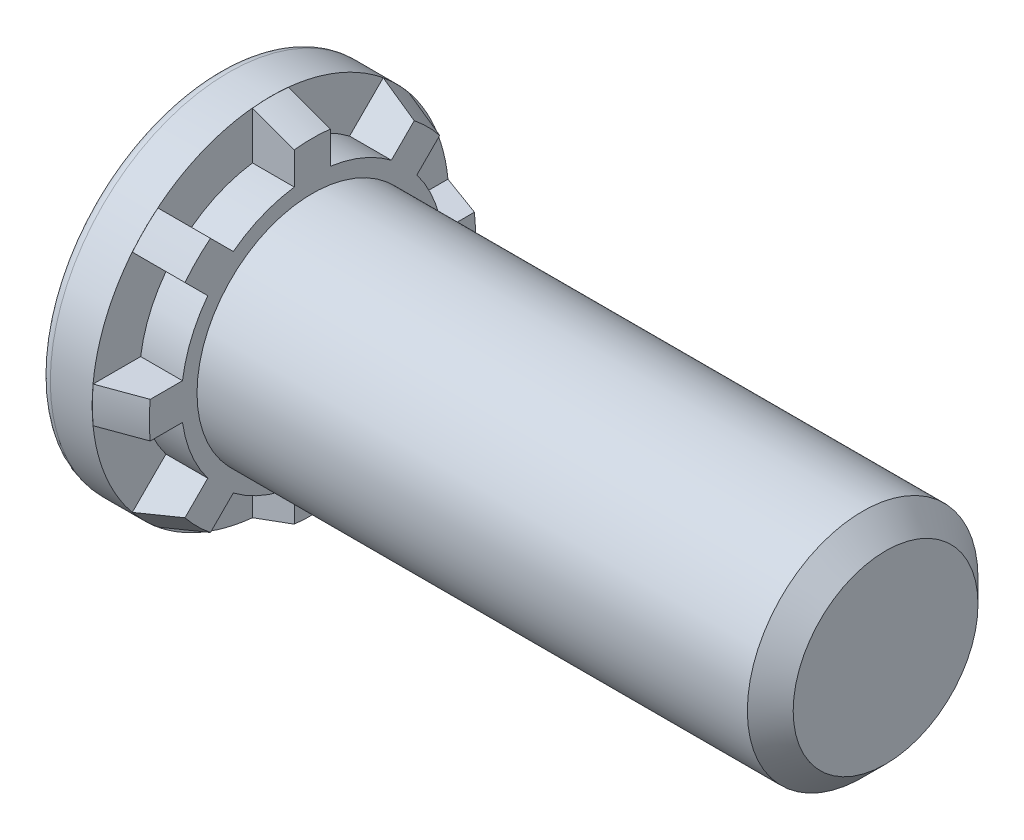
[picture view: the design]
ISO-10303-21;
HEADER;
FILE_DESCRIPTION(('STEP AP214'),'2;1');
FILE_NAME('part.step','',(''),(''),'','','');
FILE_SCHEMA(('AUTOMOTIVE_DESIGN { 1 0 10303 214 1 1 1 1 }'));
ENDSEC;
DATA;
#1=APPLICATION_CONTEXT('core data for automotive mechanical design processes');
#2=APPLICATION_PROTOCOL_DEFINITION('international standard','automotive_design',2000,#1);
#3=PRODUCT_CONTEXT('',#1,'mechanical');
#4=PRODUCT('Part','Part','',(#3));
#5=PRODUCT_RELATED_PRODUCT_CATEGORY('part','',(#4));
#6=PRODUCT_DEFINITION_FORMATION('','',#4);
#7=PRODUCT_DEFINITION_CONTEXT('part definition',#1,'design');
#8=PRODUCT_DEFINITION('design','',#6,#7);
#9=PRODUCT_DEFINITION_SHAPE('','',#8);
#10=(LENGTH_UNIT() NAMED_UNIT(*) SI_UNIT(.MILLI.,.METRE.));
#11=(NAMED_UNIT(*) PLANE_ANGLE_UNIT() SI_UNIT($,.RADIAN.));
#12=(NAMED_UNIT(*) SI_UNIT($,.STERADIAN.) SOLID_ANGLE_UNIT());
#13=UNCERTAINTY_MEASURE_WITH_UNIT(LENGTH_MEASURE(1.E-05),#10,'distance_accuracy_value','');
#14=(GEOMETRIC_REPRESENTATION_CONTEXT(3) GLOBAL_UNCERTAINTY_ASSIGNED_CONTEXT((#13)) GLOBAL_UNIT_ASSIGNED_CONTEXT((#10,
#11,#12)) REPRESENTATION_CONTEXT('',''));
#15=CARTESIAN_POINT('',(0.,0.,0.));
#16=DIRECTION('',(0.,0.,1.));
#17=DIRECTION('',(1.,0.,0.));
#18=AXIS2_PLACEMENT_3D('',#15,#16,#17);
#19=CARTESIAN_POINT('',(0.00254,0.,0.));
#20=DIRECTION('',(-1.,0.,0.));
#21=DIRECTION('',(0.,0.,1.));
#22=AXIS2_PLACEMENT_3D('',#19,#20,#21);
#23=CONICAL_SURFACE('',#22,7.36346,0.349065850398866);
#24=CARTESIAN_POINT('',(1.72739999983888,4.20680011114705,5.26041628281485));
#25=CARTESIAN_POINT('',(1.43990711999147,4.28124598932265,5.33486216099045));
#26=CARTESIAN_POINT('',(1.15240568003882,4.35567533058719,5.40929150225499));
#27=CARTESIAN_POINT('',(0.577385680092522,4.5045009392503,5.55811711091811));
#28=CARTESIAN_POINT('',(0.28986712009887,4.57889720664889,5.6325133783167));
#29=CARTESIAN_POINT('',(0.00233999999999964,4.65327693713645,5.70689310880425));
#30=B_SPLINE_CURVE_WITH_KNOTS('',3,(#24,#25,#26,#27,#28,#29),.UNSPECIFIED.,.F.,.F.,(4,2,4),(0.,
0.918492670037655,1.83698533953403),.UNSPECIFIED.);
#31=CARTESIAN_POINT('',(1.72719999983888,4.20685190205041,5.26046807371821));
#32=VERTEX_POINT('',#31);
#33=CARTESIAN_POINT('',(0.00254,4.65322519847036,5.70684137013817));
#34=VERTEX_POINT('',#33);
#35=EDGE_CURVE('E558',#32,#34,#30,.T.);
#36=ORIENTED_EDGE('',*,*,#35,.F.);
#37=CARTESIAN_POINT('',(1.7272,0.,0.));
#38=DIRECTION('',(-1.,0.,0.));
#39=DIRECTION('',(0.,0.,1.));
#40=AXIS2_PLACEMENT_3D('',#37,#38,#39);
#41=CIRCLE('',#40,6.73573509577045);
#42=CARTESIAN_POINT('',(1.72719999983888,5.2604680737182,4.20685190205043));
#43=VERTEX_POINT('',#42);
#44=EDGE_CURVE('E559',#32,#43,#41,.T.);
#45=ORIENTED_EDGE('',*,*,#44,.T.);
#46=CARTESIAN_POINT('',(0.00234000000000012,5.70689310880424,4.65327693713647));
#47=CARTESIAN_POINT('',(0.28986712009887,5.63251337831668,4.57889720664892));
#48=CARTESIAN_POINT('',(0.577385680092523,5.55811711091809,4.50450093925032));
#49=CARTESIAN_POINT('',(1.15240568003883,5.40929150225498,4.35567533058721));
#50=CARTESIAN_POINT('',(1.43990711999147,5.33486216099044,4.28124598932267));
#51=CARTESIAN_POINT('',(1.72739999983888,5.26041628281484,4.20680011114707));
#52=B_SPLINE_CURVE_WITH_KNOTS('',3,(#46,#47,#48,#49,#50,#51),.UNSPECIFIED.,.F.,.F.,(4,2,4),(0.,
0.918492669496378,1.83698533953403),.UNSPECIFIED.);
#53=CARTESIAN_POINT('',(0.00254,5.70684137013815,4.65322519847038));
#54=VERTEX_POINT('',#53);
#55=EDGE_CURVE('E457',#54,#43,#52,.T.);
#56=ORIENTED_EDGE('',*,*,#55,.F.);
#57=CARTESIAN_POINT('',(0.00254,0.,0.));
#58=DIRECTION('',(-1.,0.,0.));
#59=DIRECTION('',(0.,0.,1.));
#60=AXIS2_PLACEMENT_3D('',#57,#58,#59);
#61=CIRCLE('',#60,7.36346);
#62=EDGE_CURVE('E561',#34,#54,#61,.T.);
#63=ORIENTED_EDGE('',*,*,#62,.F.);
#64=EDGE_LOOP('',(#36,#45,#56,#63));
#65=FACE_BOUND('',#64,.T.);
#66=ADVANCED_FACE('F39',(#65),#23,.T.);
#67=CARTESIAN_POINT('',(1.72739999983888,-5.26041628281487,4.20680011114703));
#68=CARTESIAN_POINT('',(1.43990711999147,-5.33486216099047,4.28124598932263));
#69=CARTESIAN_POINT('',(1.15240568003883,-5.40929150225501,4.35567533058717));
#70=CARTESIAN_POINT('',(0.577385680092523,-5.55811711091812,4.50450093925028));
#71=CARTESIAN_POINT('',(0.28986712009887,-5.63251337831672,4.57889720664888));
#72=CARTESIAN_POINT('',(0.00234000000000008,-5.70689310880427,4.65327693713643));
#73=B_SPLINE_CURVE_WITH_KNOTS('',3,(#67,#68,#69,#70,#71,#72),.UNSPECIFIED.,.F.,.F.,(4,2,4),(0.,
0.918492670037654,1.83698533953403),.UNSPECIFIED.);
#74=CARTESIAN_POINT('',(1.72719999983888,-5.26046807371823,4.20685190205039));
#75=VERTEX_POINT('',#74);
#76=CARTESIAN_POINT('',(0.00254,-5.70684137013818,4.65322519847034));
#77=VERTEX_POINT('',#76);
#78=EDGE_CURVE('E607',#75,#77,#73,.T.);
#79=ORIENTED_EDGE('',*,*,#78,.F.);
#80=CARTESIAN_POINT('',(1.72719999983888,-4.20685190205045,5.26046807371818));
#81=VERTEX_POINT('',#80);
#82=EDGE_CURVE('E572',#75,#81,#41,.T.);
#83=ORIENTED_EDGE('',*,*,#82,.T.);
#84=CARTESIAN_POINT('',(0.00234000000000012,-4.65327693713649,5.70689310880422));
#85=CARTESIAN_POINT('',(0.28986712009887,-4.57889720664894,5.63251337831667));
#86=CARTESIAN_POINT('',(0.577385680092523,-4.50450093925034,5.55811711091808));
#87=CARTESIAN_POINT('',(1.15240568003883,-4.35567533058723,5.40929150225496));
#88=CARTESIAN_POINT('',(1.43990711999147,-4.28124598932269,5.33486216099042));
#89=CARTESIAN_POINT('',(1.72739999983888,-4.20680011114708,5.26041628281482));
#90=B_SPLINE_CURVE_WITH_KNOTS('',3,(#84,#85,#86,#87,#88,#89),.UNSPECIFIED.,.F.,.F.,(4,2,4),(0.,
0.918492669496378,1.83698533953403),.UNSPECIFIED.);
#91=CARTESIAN_POINT('',(0.00254,-4.6532251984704,5.70684137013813));
#92=VERTEX_POINT('',#91);
#93=EDGE_CURVE('E610',#92,#81,#90,.T.);
#94=ORIENTED_EDGE('',*,*,#93,.F.);
#95=EDGE_CURVE('E750',#77,#92,#61,.T.);
#96=ORIENTED_EDGE('',*,*,#95,.F.);
#97=EDGE_LOOP('',(#79,#83,#94,#96));
#98=FACE_BOUND('',#97,.T.);
#99=ADVANCED_FACE('F550',(#98),#23,.T.);
#100=CARTESIAN_POINT('',(-4.27246553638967,0.74501913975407,8.88826546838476));
#101=CARTESIAN_POINT('',(-3.51512222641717,0.745019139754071,8.61164424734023));
#102=CARTESIAN_POINT('',(-2.75780524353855,0.745019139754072,8.33495090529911));
#103=CARTESIAN_POINT('',(-1.24325020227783,0.745019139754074,7.78134871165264));
#104=CARTESIAN_POINT('',(-0.4860121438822,0.745019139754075,7.50443986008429));
#105=CARTESIAN_POINT('',(1.02835911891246,0.745019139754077,6.95033525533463));
#106=CARTESIAN_POINT('',(1.78549232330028,0.745019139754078,6.67313950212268));
#107=CARTESIAN_POINT('',(3.29960004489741,0.74501913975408,6.11831457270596));
#108=CARTESIAN_POINT('',(4.05657456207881,0.745019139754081,5.84068539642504));
#109=CARTESIAN_POINT('',(4.81344272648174,0.745019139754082,5.56276628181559));
#110=B_SPLINE_CURVE_WITH_KNOTS('',3,(#100,#101,#102,#103,#104,#105,#106,#107,#108,#109),
.UNSPECIFIED.,.F.,.F.,(4,2,2,2,4),(0.,2.41884141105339,4.83768240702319,7.25652366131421,
9.67536534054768),.UNSPECIFIED.);
#111=CARTESIAN_POINT('',(0.00254,0.745019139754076,7.32567332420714));
#112=VERTEX_POINT('',#111);
#113=CARTESIAN_POINT('',(1.72719999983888,0.745019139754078,6.69440615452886));
#114=VERTEX_POINT('',#113);
#115=EDGE_CURVE('E562',#112,#114,#110,.T.);
#116=ORIENTED_EDGE('',*,*,#115,.F.);
#117=CARTESIAN_POINT('',(0.00254,-0.745019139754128,7.32567332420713));
#118=VERTEX_POINT('',#117);
#119=EDGE_CURVE('E676',#118,#112,#61,.T.);
#120=ORIENTED_EDGE('',*,*,#119,.F.);
#121=CARTESIAN_POINT('',(4.81344272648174,-0.745019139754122,5.56276628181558));
#122=CARTESIAN_POINT('',(4.05657456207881,-0.745019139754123,5.84068539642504));
#123=CARTESIAN_POINT('',(3.29960004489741,-0.745019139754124,6.11831457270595));
#124=CARTESIAN_POINT('',(1.78549232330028,-0.745019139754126,6.67313950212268));
#125=CARTESIAN_POINT('',(1.02835911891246,-0.745019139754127,6.95033525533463));
#126=CARTESIAN_POINT('',(-0.486012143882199,-0.745019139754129,7.50443986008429));
#127=CARTESIAN_POINT('',(-1.24325020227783,-0.74501913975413,7.78134871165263));
#128=CARTESIAN_POINT('',(-2.75780524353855,-0.745019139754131,8.3349509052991));
#129=CARTESIAN_POINT('',(-3.51512222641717,-0.745019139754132,8.61164424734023));
#130=CARTESIAN_POINT('',(-4.27246553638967,-0.745019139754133,8.88826546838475));
#131=B_SPLINE_CURVE_WITH_KNOTS('',3,(#121,#122,#123,#124,#125,#126,#127,#128,#129,#130),
.UNSPECIFIED.,.F.,.F.,(4,2,2,2,4),(0.,2.41884167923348,4.83768293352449,7.25652392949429,
9.67536534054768),.UNSPECIFIED.);
#132=CARTESIAN_POINT('',(1.72719999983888,-0.745019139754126,6.69440615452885));
#133=VERTEX_POINT('',#132);
#134=EDGE_CURVE('E630',#133,#118,#131,.T.);
#135=ORIENTED_EDGE('',*,*,#134,.F.);
#136=EDGE_CURVE('E568',#133,#114,#41,.T.);
#137=ORIENTED_EDGE('',*,*,#136,.T.);
#138=EDGE_LOOP('',(#116,#120,#135,#137));
#139=FACE_BOUND('',#138,.T.);
#140=ADVANCED_FACE('F552',(#139),#23,.T.);
#141=CARTESIAN_POINT('',(4.81344272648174,0.74501913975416,-5.56276628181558));
#142=CARTESIAN_POINT('',(4.05657456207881,0.745019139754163,-5.84068539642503));
#143=CARTESIAN_POINT('',(3.29960004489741,0.745019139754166,-6.11831457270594));
#144=CARTESIAN_POINT('',(1.78549232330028,0.745019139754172,-6.67313950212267));
#145=CARTESIAN_POINT('',(1.02835911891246,0.745019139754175,-6.95033525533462));
#146=CARTESIAN_POINT('',(-0.486012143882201,0.745019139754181,-7.50443986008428));
#147=CARTESIAN_POINT('',(-1.24325020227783,0.745019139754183,-7.78134871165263));
#148=CARTESIAN_POINT('',(-2.75780524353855,0.745019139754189,-8.3349509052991));
#149=CARTESIAN_POINT('',(-3.51512222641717,0.745019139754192,-8.61164424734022));
#150=CARTESIAN_POINT('',(-4.27246553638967,0.745019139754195,-8.88826546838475));
#151=B_SPLINE_CURVE_WITH_KNOTS('',3,(#141,#142,#143,#144,#145,#146,#147,#148,#149,#150),
.UNSPECIFIED.,.F.,.F.,(4,2,2,2,4),(0.,2.41884167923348,4.83768293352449,7.2565239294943,
9.67536534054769),.UNSPECIFIED.);
#152=CARTESIAN_POINT('',(1.72719999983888,0.745019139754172,-6.69440615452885));
#153=VERTEX_POINT('',#152);
#154=CARTESIAN_POINT('',(0.00254,0.745019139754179,-7.32567332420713));
#155=VERTEX_POINT('',#154);
#156=EDGE_CURVE('E693',#153,#155,#151,.T.);
#157=ORIENTED_EDGE('',*,*,#156,.F.);
#158=CARTESIAN_POINT('',(1.72719999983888,-0.745019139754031,-6.69440615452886));
#159=VERTEX_POINT('',#158);
#160=EDGE_CURVE('E574',#153,#159,#41,.T.);
#161=ORIENTED_EDGE('',*,*,#160,.T.);
#162=CARTESIAN_POINT('',(-4.27246553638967,-0.745019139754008,-8.88826546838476));
#163=CARTESIAN_POINT('',(-3.51512222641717,-0.745019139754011,-8.61164424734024));
#164=CARTESIAN_POINT('',(-2.75780524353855,-0.745019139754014,-8.33495090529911));
#165=CARTESIAN_POINT('',(-1.24325020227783,-0.74501913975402,-7.78134871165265));
#166=CARTESIAN_POINT('',(-0.4860121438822,-0.745019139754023,-7.5044398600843));
#167=CARTESIAN_POINT('',(1.02835911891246,-0.745019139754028,-6.95033525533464));
#168=CARTESIAN_POINT('',(1.78549232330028,-0.745019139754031,-6.67313950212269));
#169=CARTESIAN_POINT('',(3.29960004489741,-0.745019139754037,-6.11831457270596));
#170=CARTESIAN_POINT('',(4.05657456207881,-0.74501913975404,-5.84068539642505));
#171=CARTESIAN_POINT('',(4.81344272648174,-0.745019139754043,-5.56276628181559));
#172=B_SPLINE_CURVE_WITH_KNOTS('',3,(#162,#163,#164,#165,#166,#167,#168,#169,#170,#171),
.UNSPECIFIED.,.F.,.F.,(4,2,2,2,4),(0.,2.41884141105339,4.83768240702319,7.25652366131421,
9.67536534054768),.UNSPECIFIED.);
#173=CARTESIAN_POINT('',(0.00254,-0.745019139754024,-7.32567332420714));
#174=VERTEX_POINT('',#173);
#175=EDGE_CURVE('E700',#174,#159,#172,.T.);
#176=ORIENTED_EDGE('',*,*,#175,.F.);
#177=EDGE_CURVE('E673',#155,#174,#61,.T.);
#178=ORIENTED_EDGE('',*,*,#177,.F.);
#179=EDGE_LOOP('',(#157,#161,#176,#178));
#180=FACE_BOUND('',#179,.T.);
#181=ADVANCED_FACE('F935',(#180),#23,.T.);
#182=CARTESIAN_POINT('',(1.72739999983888,-4.20680011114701,-5.26041628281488));
#183=CARTESIAN_POINT('',(1.43990711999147,-4.28124598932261,-5.33486216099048));
#184=CARTESIAN_POINT('',(1.15240568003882,-4.35567533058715,-5.40929150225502));
#185=CARTESIAN_POINT('',(0.577385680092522,-4.50450093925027,-5.55811711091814));
#186=CARTESIAN_POINT('',(0.28986712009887,-4.57889720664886,-5.63251337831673));
#187=CARTESIAN_POINT('',(0.00233999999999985,-4.65327693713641,-5.70689310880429));
#188=B_SPLINE_CURVE_WITH_KNOTS('',3,(#182,#183,#184,#185,#186,#187),.UNSPECIFIED.,.F.,.F.,(4,2,
4),(0.,0.918492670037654,1.83698533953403),.UNSPECIFIED.);
#189=CARTESIAN_POINT('',(1.72719999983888,-4.20685190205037,-5.26046807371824));
#190=VERTEX_POINT('',#189);
#191=CARTESIAN_POINT('',(0.00254,-4.65322519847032,-5.7068413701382));
#192=VERTEX_POINT('',#191);
#193=EDGE_CURVE('E692',#190,#192,#188,.T.);
#194=ORIENTED_EDGE('',*,*,#193,.F.);
#195=CARTESIAN_POINT('',(1.72719999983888,-5.26046807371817,-4.20685190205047));
#196=VERTEX_POINT('',#195);
#197=EDGE_CURVE('E588',#190,#196,#41,.T.);
#198=ORIENTED_EDGE('',*,*,#197,.T.);
#199=CARTESIAN_POINT('',(0.00234000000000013,-5.7068931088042,-4.65327693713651));
#200=CARTESIAN_POINT('',(0.28986712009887,-5.63251337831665,-4.57889720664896));
#201=CARTESIAN_POINT('',(0.577385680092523,-5.55811711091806,-4.50450093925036));
#202=CARTESIAN_POINT('',(1.15240568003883,-5.40929150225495,-4.35567533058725));
#203=CARTESIAN_POINT('',(1.43990711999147,-5.33486216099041,-4.2812459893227));
#204=CARTESIAN_POINT('',(1.72739999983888,-5.26041628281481,-4.2068001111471));
#205=B_SPLINE_CURVE_WITH_KNOTS('',3,(#199,#200,#201,#202,#203,#204),.UNSPECIFIED.,.F.,.F.,(4,2,
4),(0.,0.918492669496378,1.83698533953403),.UNSPECIFIED.);
#206=CARTESIAN_POINT('',(0.00254,-5.70684137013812,-4.65322519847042));
#207=VERTEX_POINT('',#206);
#208=EDGE_CURVE('E330',#207,#196,#205,.T.);
#209=ORIENTED_EDGE('',*,*,#208,.F.);
#210=EDGE_CURVE('E680',#192,#207,#61,.T.);
#211=ORIENTED_EDGE('',*,*,#210,.F.);
#212=EDGE_LOOP('',(#194,#198,#209,#211));
#213=FACE_BOUND('',#212,.T.);
#214=ADVANCED_FACE('F928',(#213),#23,.T.);
#215=CARTESIAN_POINT('',(-4.27246553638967,-8.88826546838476,0.745019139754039));
#216=CARTESIAN_POINT('',(-3.51512222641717,-8.61164424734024,0.745019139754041));
#217=CARTESIAN_POINT('',(-2.75780524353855,-8.33495090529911,0.745019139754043));
#218=CARTESIAN_POINT('',(-1.24325020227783,-7.78134871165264,0.745019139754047));
#219=CARTESIAN_POINT('',(-0.486012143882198,-7.5044398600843,0.745019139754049));
#220=CARTESIAN_POINT('',(1.02835911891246,-6.95033525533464,0.745019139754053));
#221=CARTESIAN_POINT('',(1.78549232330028,-6.67313950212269,0.745019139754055));
#222=CARTESIAN_POINT('',(3.29960004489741,-6.11831457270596,0.745019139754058));
#223=CARTESIAN_POINT('',(4.05657456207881,-5.84068539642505,0.74501913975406));
#224=CARTESIAN_POINT('',(4.81344272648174,-5.56276628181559,0.745019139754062));
#225=B_SPLINE_CURVE_WITH_KNOTS('',3,(#215,#216,#217,#218,#219,#220,#221,#222,#223,#224),
.UNSPECIFIED.,.F.,.F.,(4,2,2,2,4),(0.,2.41884141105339,4.83768240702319,7.25652366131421,
9.67536534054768),.UNSPECIFIED.);
#226=CARTESIAN_POINT('',(0.00254,-7.32567332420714,0.74501913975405));
#227=VERTEX_POINT('',#226);
#228=CARTESIAN_POINT('',(1.72719999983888,-6.69440615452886,0.745019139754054));
#229=VERTEX_POINT('',#228);
#230=EDGE_CURVE('E746',#227,#229,#225,.T.);
#231=ORIENTED_EDGE('',*,*,#230,.F.);
#232=CARTESIAN_POINT('',(0.00254,-7.32567332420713,-0.745019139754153));
#233=VERTEX_POINT('',#232);
#234=EDGE_CURVE('E745',#233,#227,#61,.T.);
#235=ORIENTED_EDGE('',*,*,#234,.F.);
#236=CARTESIAN_POINT('',(4.81344272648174,-5.56276628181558,-0.745019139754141));
#237=CARTESIAN_POINT('',(4.05657456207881,-5.84068539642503,-0.745019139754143));
#238=CARTESIAN_POINT('',(3.29960004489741,-6.11831457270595,-0.745019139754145));
#239=CARTESIAN_POINT('',(1.78549232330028,-6.67313950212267,-0.745019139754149));
#240=CARTESIAN_POINT('',(1.02835911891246,-6.95033525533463,-0.745019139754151));
#241=CARTESIAN_POINT('',(-0.4860121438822,-7.50443986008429,-0.745019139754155));
#242=CARTESIAN_POINT('',(-1.24325020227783,-7.78134871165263,-0.745019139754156));
#243=CARTESIAN_POINT('',(-2.75780524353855,-8.3349509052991,-0.74501913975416));
#244=CARTESIAN_POINT('',(-3.51512222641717,-8.61164424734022,-0.745019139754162));
#245=CARTESIAN_POINT('',(-4.27246553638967,-8.88826546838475,-0.745019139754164));
#246=B_SPLINE_CURVE_WITH_KNOTS('',3,(#236,#237,#238,#239,#240,#241,#242,#243,#244,#245),
.UNSPECIFIED.,.F.,.F.,(4,2,2,2,4),(0.,2.41884167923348,4.83768293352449,7.2565239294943,
9.67536534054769),.UNSPECIFIED.);
#247=CARTESIAN_POINT('',(1.72719999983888,-6.69440615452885,-0.745019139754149));
#248=VERTEX_POINT('',#247);
#249=EDGE_CURVE('E430',#248,#233,#246,.T.);
#250=ORIENTED_EDGE('',*,*,#249,.F.);
#251=EDGE_CURVE('E595',#248,#229,#41,.T.);
#252=ORIENTED_EDGE('',*,*,#251,.T.);
#253=EDGE_LOOP('',(#231,#235,#250,#252));
#254=FACE_BOUND('',#253,.T.);
#255=ADVANCED_FACE('F747',(#254),#23,.T.);
#256=CARTESIAN_POINT('',(0.,0.,0.));
#257=DIRECTION('',(-1.,0.,0.));
#258=DIRECTION('',(0.,0.,1.));
#259=AXIS2_PLACEMENT_3D('',#256,#257,#258);
#260=CYLINDRICAL_SURFACE('',#259,7.36346);
#261=CARTESIAN_POINT('',(0.,0.,0.));
#262=DIRECTION('',(-1.,0.,0.));
#263=DIRECTION('',(0.,0.,1.));
#264=AXIS2_PLACEMENT_3D('',#261,#262,#263);
#265=CIRCLE('',#264,7.36346);
#266=CARTESIAN_POINT('',(0.,4.65322519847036,5.70684137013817));
#267=VERTEX_POINT('',#266);
#268=CARTESIAN_POINT('',(-1.61121766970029E-10,5.70684137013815,4.65322519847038));
#269=VERTEX_POINT('',#268);
#270=EDGE_CURVE('E636',#267,#269,#265,.T.);
#271=ORIENTED_EDGE('',*,*,#270,.F.);
#272=DIRECTION('',(-1.,0.,0.));
#273=VECTOR('',#272,1.);
#274=CARTESIAN_POINT('',(0.,4.65322519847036,5.70684137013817));
#275=LINE('',#274,#273);
#276=EDGE_CURVE('E11',#267,#34,#275,.F.);
#277=ORIENTED_EDGE('',*,*,#276,.T.);
#278=ORIENTED_EDGE('',*,*,#62,.T.);
#279=DIRECTION('',(-1.,0.,0.));
#280=VECTOR('',#279,1.);
#281=CARTESIAN_POINT('',(0.,5.70684137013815,4.65322519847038));
#282=LINE('',#281,#280);
#283=EDGE_CURVE('E686',#54,#269,#282,.T.);
#284=ORIENTED_EDGE('',*,*,#283,.T.);
#285=EDGE_LOOP('',(#271,#277,#278,#284));
#286=FACE_BOUND('',#285,.T.);
#287=ADVANCED_FACE('F508',(#286),#260,.T.);
#288=CARTESIAN_POINT('',(0.,-5.70684137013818,4.65322519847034));
#289=VERTEX_POINT('',#288);
#290=CARTESIAN_POINT('',(-1.61121766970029E-10,-4.6532251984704,5.70684137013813));
#291=VERTEX_POINT('',#290);
#292=EDGE_CURVE('E634',#289,#291,#265,.T.);
#293=ORIENTED_EDGE('',*,*,#292,.F.);
#294=DIRECTION('',(-1.,0.,0.));
#295=VECTOR('',#294,1.);
#296=CARTESIAN_POINT('',(0.,-5.70684137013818,4.65322519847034));
#297=LINE('',#296,#295);
#298=EDGE_CURVE('E859',#289,#77,#297,.F.);
#299=ORIENTED_EDGE('',*,*,#298,.T.);
#300=ORIENTED_EDGE('',*,*,#95,.T.);
#301=DIRECTION('',(-1.,0.,0.));
#302=VECTOR('',#301,1.);
#303=CARTESIAN_POINT('',(0.,-4.6532251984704,5.70684137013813));
#304=LINE('',#303,#302);
#305=EDGE_CURVE('E635',#92,#291,#304,.T.);
#306=ORIENTED_EDGE('',*,*,#305,.T.);
#307=EDGE_LOOP('',(#293,#299,#300,#306));
#308=FACE_BOUND('',#307,.T.);
#309=ADVANCED_FACE('F865',(#308),#260,.T.);
#310=ORIENTED_EDGE('',*,*,#119,.T.);
#311=DIRECTION('',(-1.,0.,0.));
#312=VECTOR('',#311,1.);
#313=CARTESIAN_POINT('',(0.,0.745019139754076,7.32567332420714));
#314=LINE('',#313,#312);
#315=CARTESIAN_POINT('',(-1.61121766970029E-10,0.745019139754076,7.32567332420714));
#316=VERTEX_POINT('',#315);
#317=EDGE_CURVE('E48',#112,#316,#314,.T.);
#318=ORIENTED_EDGE('',*,*,#317,.T.);
#319=CARTESIAN_POINT('',(0.,-0.745019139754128,7.32567332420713));
#320=VERTEX_POINT('',#319);
#321=EDGE_CURVE('E303',#320,#316,#265,.T.);
#322=ORIENTED_EDGE('',*,*,#321,.F.);
#323=DIRECTION('',(-1.,0.,0.));
#324=VECTOR('',#323,1.);
#325=CARTESIAN_POINT('',(0.,-0.745019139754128,7.32567332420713));
#326=LINE('',#325,#324);
#327=EDGE_CURVE('E622',#320,#118,#326,.F.);
#328=ORIENTED_EDGE('',*,*,#327,.T.);
#329=EDGE_LOOP('',(#310,#318,#322,#328));
#330=FACE_BOUND('',#329,.T.);
#331=ADVANCED_FACE('F632',(#330),#260,.T.);
#332=CARTESIAN_POINT('',(0.,0.745019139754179,-7.32567332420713));
#333=VERTEX_POINT('',#332);
#334=CARTESIAN_POINT('',(-1.61121766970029E-10,-0.745019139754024,-7.32567332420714));
#335=VERTEX_POINT('',#334);
#336=EDGE_CURVE('E641',#333,#335,#265,.T.);
#337=ORIENTED_EDGE('',*,*,#336,.F.);
#338=DIRECTION('',(-1.,0.,0.));
#339=VECTOR('',#338,1.);
#340=CARTESIAN_POINT('',(0.,0.745019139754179,-7.32567332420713));
#341=LINE('',#340,#339);
#342=EDGE_CURVE('E862',#333,#155,#341,.F.);
#343=ORIENTED_EDGE('',*,*,#342,.T.);
#344=ORIENTED_EDGE('',*,*,#177,.T.);
#345=DIRECTION('',(-1.,0.,0.));
#346=VECTOR('',#345,1.);
#347=CARTESIAN_POINT('',(0.,-0.745019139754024,-7.32567332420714));
#348=LINE('',#347,#346);
#349=EDGE_CURVE('E742',#174,#335,#348,.T.);
#350=ORIENTED_EDGE('',*,*,#349,.T.);
#351=EDGE_LOOP('',(#337,#343,#344,#350));
#352=FACE_BOUND('',#351,.T.);
#353=ADVANCED_FACE('F841',(#352),#260,.T.);
#354=CARTESIAN_POINT('',(0.,-4.65322519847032,-5.7068413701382));
#355=VERTEX_POINT('',#354);
#356=CARTESIAN_POINT('',(-1.61121766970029E-10,-5.70684137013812,-4.65322519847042));
#357=VERTEX_POINT('',#356);
#358=EDGE_CURVE('E850',#355,#357,#265,.T.);
#359=ORIENTED_EDGE('',*,*,#358,.F.);
#360=DIRECTION('',(-1.,0.,0.));
#361=VECTOR('',#360,1.);
#362=CARTESIAN_POINT('',(0.,-4.65322519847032,-5.7068413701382));
#363=LINE('',#362,#361);
#364=EDGE_CURVE('E842',#355,#192,#363,.F.);
#365=ORIENTED_EDGE('',*,*,#364,.T.);
#366=ORIENTED_EDGE('',*,*,#210,.T.);
#367=DIRECTION('',(-1.,0.,0.));
#368=VECTOR('',#367,1.);
#369=CARTESIAN_POINT('',(0.,-5.70684137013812,-4.65322519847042));
#370=LINE('',#369,#368);
#371=EDGE_CURVE('E744',#207,#357,#370,.T.);
#372=ORIENTED_EDGE('',*,*,#371,.T.);
#373=EDGE_LOOP('',(#359,#365,#366,#372));
#374=FACE_BOUND('',#373,.T.);
#375=ADVANCED_FACE('F917',(#374),#260,.T.);
#376=ORIENTED_EDGE('',*,*,#234,.T.);
#377=DIRECTION('',(-1.,0.,0.));
#378=VECTOR('',#377,1.);
#379=CARTESIAN_POINT('',(0.,-7.32567332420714,0.74501913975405));
#380=LINE('',#379,#378);
#381=CARTESIAN_POINT('',(-1.61121766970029E-10,-7.32567332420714,0.74501913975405));
#382=VERTEX_POINT('',#381);
#383=EDGE_CURVE('E631',#227,#382,#380,.T.);
#384=ORIENTED_EDGE('',*,*,#383,.T.);
#385=CARTESIAN_POINT('',(0.,-7.32567332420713,-0.745019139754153));
#386=VERTEX_POINT('',#385);
#387=EDGE_CURVE('E637',#386,#382,#265,.T.);
#388=ORIENTED_EDGE('',*,*,#387,.F.);
#389=DIRECTION('',(-1.,0.,0.));
#390=VECTOR('',#389,1.);
#391=CARTESIAN_POINT('',(0.,-7.32567332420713,-0.745019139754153));
#392=LINE('',#391,#390);
#393=EDGE_CURVE('E733',#386,#233,#392,.F.);
#394=ORIENTED_EDGE('',*,*,#393,.T.);
#395=EDGE_LOOP('',(#376,#384,#388,#394));
#396=FACE_BOUND('',#395,.T.);
#397=ADVANCED_FACE('F739',(#396),#260,.T.);
#398=CARTESIAN_POINT('',(4.81344272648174,5.56276628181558,0.745019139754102));
#399=CARTESIAN_POINT('',(4.05657456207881,5.84068539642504,0.745019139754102));
#400=CARTESIAN_POINT('',(3.29960004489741,6.11831457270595,0.745019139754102));
#401=CARTESIAN_POINT('',(1.78549232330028,6.67313950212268,0.745019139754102));
#402=CARTESIAN_POINT('',(1.02835911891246,6.95033525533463,0.745019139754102));
#403=CARTESIAN_POINT('',(-0.4860121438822,7.50443986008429,0.745019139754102));
#404=CARTESIAN_POINT('',(-1.24325020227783,7.78134871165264,0.745019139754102));
#405=CARTESIAN_POINT('',(-2.75780524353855,8.3349509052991,0.745019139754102));
#406=CARTESIAN_POINT('',(-3.51512222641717,8.61164424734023,0.745019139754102));
#407=CARTESIAN_POINT('',(-4.27246553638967,8.88826546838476,0.745019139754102));
#408=B_SPLINE_CURVE_WITH_KNOTS('',3,(#398,#399,#400,#401,#402,#403,#404,#405,#406,#407),
.UNSPECIFIED.,.F.,.F.,(4,2,2,2,4),(0.,2.41884167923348,4.83768293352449,7.25652392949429,
9.67536534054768),.UNSPECIFIED.);
#409=CARTESIAN_POINT('',(1.72719999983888,6.69440615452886,0.745019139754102));
#410=VERTEX_POINT('',#409);
#411=CARTESIAN_POINT('',(0.00254,7.32567332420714,0.745019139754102));
#412=VERTEX_POINT('',#411);
#413=EDGE_CURVE('E451',#410,#412,#408,.T.);
#414=ORIENTED_EDGE('',*,*,#413,.F.);
#415=CARTESIAN_POINT('',(1.72719999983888,6.69440615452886,-0.745019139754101));
#416=VERTEX_POINT('',#415);
#417=EDGE_CURVE('E567',#410,#416,#41,.T.);
#418=ORIENTED_EDGE('',*,*,#417,.T.);
#419=CARTESIAN_POINT('',(-4.27246553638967,8.88826546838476,-0.745019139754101));
#420=CARTESIAN_POINT('',(-3.51512222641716,8.61164424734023,-0.745019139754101));
#421=CARTESIAN_POINT('',(-2.75780524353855,8.3349509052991,-0.745019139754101));
#422=CARTESIAN_POINT('',(-1.24325020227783,7.78134871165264,-0.745019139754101));
#423=CARTESIAN_POINT('',(-0.486012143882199,7.50443986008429,-0.745019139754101));
#424=CARTESIAN_POINT('',(1.02835911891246,6.95033525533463,-0.745019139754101));
#425=CARTESIAN_POINT('',(1.78549232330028,6.67313950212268,-0.745019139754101));
#426=CARTESIAN_POINT('',(3.29960004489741,6.11831457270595,-0.745019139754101));
#427=CARTESIAN_POINT('',(4.05657456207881,5.84068539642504,-0.745019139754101));
#428=CARTESIAN_POINT('',(4.81344272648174,5.56276628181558,-0.745019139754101));
#429=B_SPLINE_CURVE_WITH_KNOTS('',3,(#419,#420,#421,#422,#423,#424,#425,#426,#427,#428),
.UNSPECIFIED.,.F.,.F.,(4,2,2,2,4),(0.,2.41884141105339,4.83768240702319,7.2565236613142,
9.67536534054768),.UNSPECIFIED.);
#430=CARTESIAN_POINT('',(0.00254,7.32567332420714,-0.745019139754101));
#431=VERTEX_POINT('',#430);
#432=EDGE_CURVE('E483',#431,#416,#429,.T.);
#433=ORIENTED_EDGE('',*,*,#432,.F.);
#434=EDGE_CURVE('E675',#412,#431,#61,.T.);
#435=ORIENTED_EDGE('',*,*,#434,.F.);
#436=EDGE_LOOP('',(#414,#418,#433,#435));
#437=FACE_BOUND('',#436,.T.);
#438=ADVANCED_FACE('F541',(#437),#23,.T.);
#439=CARTESIAN_POINT('',(0.,7.32567332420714,0.745019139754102));
#440=VERTEX_POINT('',#439);
#441=CARTESIAN_POINT('',(-1.61121766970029E-10,7.32567332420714,-0.745019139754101));
#442=VERTEX_POINT('',#441);
#443=EDGE_CURVE('E638',#440,#442,#265,.T.);
#444=ORIENTED_EDGE('',*,*,#443,.F.);
#445=DIRECTION('',(-1.,0.,0.));
#446=VECTOR('',#445,1.);
#447=CARTESIAN_POINT('',(0.,7.32567332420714,0.745019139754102));
#448=LINE('',#447,#446);
#449=EDGE_CURVE('E872',#440,#412,#448,.F.);
#450=ORIENTED_EDGE('',*,*,#449,.T.);
#451=ORIENTED_EDGE('',*,*,#434,.T.);
#452=DIRECTION('',(-1.,0.,0.));
#453=VECTOR('',#452,1.);
#454=CARTESIAN_POINT('',(0.,7.32567332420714,-0.745019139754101));
#455=LINE('',#454,#453);
#456=EDGE_CURVE('E576',#431,#442,#455,.T.);
#457=ORIENTED_EDGE('',*,*,#456,.T.);
#458=EDGE_LOOP('',(#444,#450,#451,#457));
#459=FACE_BOUND('',#458,.T.);
#460=ADVANCED_FACE('F509',(#459),#260,.T.);
#461=CARTESIAN_POINT('',(0.00233999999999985,4.65327693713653,-5.70689310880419));
#462=CARTESIAN_POINT('',(0.28986712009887,4.57889720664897,-5.63251337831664));
#463=CARTESIAN_POINT('',(0.577385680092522,4.50450093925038,-5.55811711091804));
#464=CARTESIAN_POINT('',(1.15240568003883,4.35567533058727,-5.40929150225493));
#465=CARTESIAN_POINT('',(1.43990711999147,4.28124598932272,-5.33486216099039));
#466=CARTESIAN_POINT('',(1.72739999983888,4.20680011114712,-5.26041628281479));
#467=B_SPLINE_CURVE_WITH_KNOTS('',3,(#461,#462,#463,#464,#465,#466),.UNSPECIFIED.,.F.,.F.,(4,2,
4),(0.,0.918492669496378,1.83698533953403),.UNSPECIFIED.);
#468=CARTESIAN_POINT('',(0.00254,4.65322519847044,-5.7068413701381));
#469=VERTEX_POINT('',#468);
#470=CARTESIAN_POINT('',(1.72719999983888,4.20685190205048,-5.26046807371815));
#471=VERTEX_POINT('',#470);
#472=EDGE_CURVE('E687',#469,#471,#467,.T.);
#473=ORIENTED_EDGE('',*,*,#472,.F.);
#474=CARTESIAN_POINT('',(0.00254,5.70684137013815,-4.65322519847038));
#475=VERTEX_POINT('',#474);
#476=EDGE_CURVE('E643',#475,#469,#61,.T.);
#477=ORIENTED_EDGE('',*,*,#476,.F.);
#478=CARTESIAN_POINT('',(1.72739999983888,5.26041628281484,-4.20680011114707));
#479=CARTESIAN_POINT('',(1.43990711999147,5.33486216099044,-4.28124598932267));
#480=CARTESIAN_POINT('',(1.15240568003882,5.40929150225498,-4.35567533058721));
#481=CARTESIAN_POINT('',(0.577385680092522,5.55811711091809,-4.50450093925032));
#482=CARTESIAN_POINT('',(0.289867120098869,5.63251337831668,-4.57889720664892));
#483=CARTESIAN_POINT('',(0.00233999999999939,5.70689310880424,-4.65327693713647));
#484=B_SPLINE_CURVE_WITH_KNOTS('',3,(#478,#479,#480,#481,#482,#483),.UNSPECIFIED.,.F.,.F.,(4,2,
4),(0.,0.918492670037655,1.83698533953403),.UNSPECIFIED.);
#485=CARTESIAN_POINT('',(1.72719999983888,5.2604680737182,-4.20685190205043));
#486=VERTEX_POINT('',#485);
#487=EDGE_CURVE('E493',#486,#475,#484,.T.);
#488=ORIENTED_EDGE('',*,*,#487,.F.);
#489=EDGE_CURVE('E571',#486,#471,#41,.T.);
#490=ORIENTED_EDGE('',*,*,#489,.T.);
#491=EDGE_LOOP('',(#473,#477,#488,#490));
#492=FACE_BOUND('',#491,.T.);
#493=ADVANCED_FACE('F41',(#492),#23,.T.);
#494=CARTESIAN_POINT('',(1.7272,6.73573509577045,0.));
#495=DIRECTION('',(1.,0.,0.));
#496=DIRECTION('',(0.,0.,-1.));
#497=AXIS2_PLACEMENT_3D('',#494,#495,#496);
#498=PLANE('',#497);
#499=DIRECTION('',(0.,0.707106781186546,0.707106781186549));
#500=VECTOR('',#499,1.);
#501=CARTESIAN_POINT('',(1.72719999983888,3.26460163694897,4.31821780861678));
#502=LINE('',#501,#500);
#503=CARTESIAN_POINT('',(1.72719999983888,3.26460163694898,4.31821780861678));
#504=VERTEX_POINT('',#503);
#505=EDGE_CURVE('E306',#504,#32,#502,.T.);
#506=ORIENTED_EDGE('',*,*,#505,.F.);
#507=CARTESIAN_POINT('',(1.72719999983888,0.,0.));
#508=DIRECTION('',(-1.,0.,0.));
#509=DIRECTION('',(0.,1.,0.));
#510=AXIS2_PLACEMENT_3D('',#507,#508,#509);
#511=CIRCLE('',#510,5.413375);
#512=CARTESIAN_POINT('',(1.72719999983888,0.745019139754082,5.36186305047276));
#513=VERTEX_POINT('',#512);
#514=EDGE_CURVE('E322',#513,#504,#511,.T.);
#515=ORIENTED_EDGE('',*,*,#514,.F.);
#516=DIRECTION('',(0.,0.,-1.));
#517=VECTOR('',#516,1.);
#518=CARTESIAN_POINT('',(1.72719999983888,0.745019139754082,5.36186305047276));
#519=LINE('',#518,#517);
#520=EDGE_CURVE('E315',#114,#513,#519,.T.);
#521=ORIENTED_EDGE('',*,*,#520,.F.);
#522=ORIENTED_EDGE('',*,*,#136,.F.);
#523=DIRECTION('',(0.,0.,1.));
#524=VECTOR('',#523,1.);
#525=CARTESIAN_POINT('',(1.72719999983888,-0.745019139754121,5.36186305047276));
#526=LINE('',#525,#524);
#527=CARTESIAN_POINT('',(1.72719999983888,-0.745019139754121,5.36186305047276));
#528=VERTEX_POINT('',#527);
#529=EDGE_CURVE('E351',#528,#133,#526,.T.);
#530=ORIENTED_EDGE('',*,*,#529,.F.);
#531=CARTESIAN_POINT('',(1.72719999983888,0.,0.));
#532=DIRECTION('',(-1.,0.,0.));
#533=DIRECTION('',(0.,0.707106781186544,0.707106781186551));
#534=AXIS2_PLACEMENT_3D('',#531,#532,#533);
#535=CIRCLE('',#534,5.413375);
#536=CARTESIAN_POINT('',(1.72719999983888,-3.26460163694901,4.31821780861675));
#537=VERTEX_POINT('',#536);
#538=EDGE_CURVE('E356',#537,#528,#535,.T.);
#539=ORIENTED_EDGE('',*,*,#538,.F.);
#540=DIRECTION('',(0.,0.707106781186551,-0.707106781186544));
#541=VECTOR('',#540,1.);
#542=CARTESIAN_POINT('',(1.72719999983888,-3.26460163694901,4.31821780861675));
#543=LINE('',#542,#541);
#544=EDGE_CURVE('E350',#81,#537,#543,.T.);
#545=ORIENTED_EDGE('',*,*,#544,.F.);
#546=ORIENTED_EDGE('',*,*,#82,.F.);
#547=DIRECTION('',(0.,-0.707106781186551,0.707106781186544));
#548=VECTOR('',#547,1.);
#549=CARTESIAN_POINT('',(1.72719999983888,-4.31821780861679,3.26460163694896));
#550=LINE('',#549,#548);
#551=CARTESIAN_POINT('',(1.72719999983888,-4.31821780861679,3.26460163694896));
#552=VERTEX_POINT('',#551);
#553=EDGE_CURVE('E335',#552,#75,#550,.T.);
#554=ORIENTED_EDGE('',*,*,#553,.F.);
#555=CARTESIAN_POINT('',(1.72719999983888,0.,0.));
#556=DIRECTION('',(-1.,0.,0.));
#557=DIRECTION('',(0.,0.,1.));
#558=AXIS2_PLACEMENT_3D('',#555,#556,#557);
#559=CIRCLE('',#558,5.413375);
#560=CARTESIAN_POINT('',(1.72719999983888,-5.36186305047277,0.745019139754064));
#561=VERTEX_POINT('',#560);
#562=EDGE_CURVE('E338',#561,#552,#559,.T.);
#563=ORIENTED_EDGE('',*,*,#562,.F.);
#564=DIRECTION('',(0.,1.,0.));
#565=VECTOR('',#564,1.);
#566=CARTESIAN_POINT('',(1.72719999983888,-5.36186305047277,0.745019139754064));
#567=LINE('',#566,#565);
#568=EDGE_CURVE('E336',#229,#561,#567,.T.);
#569=ORIENTED_EDGE('',*,*,#568,.F.);
#570=ORIENTED_EDGE('',*,*,#251,.F.);
#571=DIRECTION('',(0.,-1.,0.));
#572=VECTOR('',#571,1.);
#573=CARTESIAN_POINT('',(1.72719999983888,-5.36186305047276,-0.74501913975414));
#574=LINE('',#573,#572);
#575=CARTESIAN_POINT('',(1.72719999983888,-5.36186305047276,-0.74501913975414));
#576=VERTEX_POINT('',#575);
#577=EDGE_CURVE('E410',#576,#248,#574,.T.);
#578=ORIENTED_EDGE('',*,*,#577,.F.);
#579=CARTESIAN_POINT('',(1.72719999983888,0.,0.));
#580=DIRECTION('',(-1.,0.,0.));
#581=DIRECTION('',(0.,-0.707106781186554,0.707106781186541));
#582=AXIS2_PLACEMENT_3D('',#579,#580,#581);
#583=CIRCLE('',#582,5.413375);
#584=CARTESIAN_POINT('',(1.72719999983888,-4.31821780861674,-3.26460163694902));
#585=VERTEX_POINT('',#584);
#586=EDGE_CURVE('E412',#585,#576,#583,.T.);
#587=ORIENTED_EDGE('',*,*,#586,.F.);
#588=DIRECTION('',(0.,0.707106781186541,0.707106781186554));
#589=VECTOR('',#588,1.);
#590=CARTESIAN_POINT('',(1.72719999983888,-4.31821780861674,-3.26460163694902));
#591=LINE('',#590,#589);
#592=EDGE_CURVE('E384',#196,#585,#591,.T.);
#593=ORIENTED_EDGE('',*,*,#592,.F.);
#594=ORIENTED_EDGE('',*,*,#197,.F.);
#595=DIRECTION('',(0.,-0.707106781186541,-0.707106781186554));
#596=VECTOR('',#595,1.);
#597=CARTESIAN_POINT('',(1.72719999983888,-3.26460163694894,-4.3182178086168));
#598=LINE('',#597,#596);
#599=CARTESIAN_POINT('',(1.72719999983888,-3.26460163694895,-4.3182178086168));
#600=VERTEX_POINT('',#599);
#601=EDGE_CURVE('E368',#600,#190,#598,.T.);
#602=ORIENTED_EDGE('',*,*,#601,.F.);
#603=CARTESIAN_POINT('',(1.72719999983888,0.,0.));
#604=DIRECTION('',(-1.,0.,0.));
#605=DIRECTION('',(0.,-1.,0.));
#606=AXIS2_PLACEMENT_3D('',#603,#604,#605);
#607=CIRCLE('',#606,5.413375);
#608=CARTESIAN_POINT('',(1.72719999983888,-0.745019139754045,-5.36186305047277));
#609=VERTEX_POINT('',#608);
#610=EDGE_CURVE('E376',#609,#600,#607,.T.);
#611=ORIENTED_EDGE('',*,*,#610,.F.);
#612=DIRECTION('',(0.,0.,1.));
#613=VECTOR('',#612,1.);
#614=CARTESIAN_POINT('',(1.72719999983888,-0.745019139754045,-5.36186305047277));
#615=LINE('',#614,#613);
#616=EDGE_CURVE('E372',#159,#609,#615,.T.);
#617=ORIENTED_EDGE('',*,*,#616,.F.);
#618=ORIENTED_EDGE('',*,*,#160,.F.);
#619=DIRECTION('',(0.,0.,-1.));
#620=VECTOR('',#619,1.);
#621=CARTESIAN_POINT('',(1.72719999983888,0.745019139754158,-5.36186305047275));
#622=LINE('',#621,#620);
#623=CARTESIAN_POINT('',(1.72719999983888,0.745019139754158,-5.36186305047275));
#624=VERTEX_POINT('',#623);
#625=EDGE_CURVE('E388',#624,#153,#622,.T.);
#626=ORIENTED_EDGE('',*,*,#625,.F.);
#627=CARTESIAN_POINT('',(1.72719999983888,0.,0.));
#628=DIRECTION('',(-1.,0.,0.));
#629=DIRECTION('',(0.,-0.707106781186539,-0.707106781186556));
#630=AXIS2_PLACEMENT_3D('',#627,#628,#629);
#631=CIRCLE('',#630,5.413375);
#632=CARTESIAN_POINT('',(1.72719999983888,3.26460163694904,-4.31821780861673));
#633=VERTEX_POINT('',#632);
#634=EDGE_CURVE('E400',#633,#624,#631,.T.);
#635=ORIENTED_EDGE('',*,*,#634,.F.);
#636=DIRECTION('',(0.,-0.707106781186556,0.707106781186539));
#637=VECTOR('',#636,1.);
#638=CARTESIAN_POINT('',(1.72719999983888,3.26460163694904,-4.31821780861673));
#639=LINE('',#638,#637);
#640=EDGE_CURVE('E394',#471,#633,#639,.T.);
#641=ORIENTED_EDGE('',*,*,#640,.F.);
#642=ORIENTED_EDGE('',*,*,#489,.F.);
#643=DIRECTION('',(0.,0.707106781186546,-0.707106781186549));
#644=VECTOR('',#643,1.);
#645=CARTESIAN_POINT('',(1.72719999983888,4.31821780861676,-3.26460163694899));
#646=LINE('',#645,#644);
#647=CARTESIAN_POINT('',(1.72719999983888,4.31821780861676,-3.26460163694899));
#648=VERTEX_POINT('',#647);
#649=EDGE_CURVE('E466',#648,#486,#646,.T.);
#650=ORIENTED_EDGE('',*,*,#649,.F.);
#651=CARTESIAN_POINT('',(1.72719999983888,0.,0.));
#652=DIRECTION('',(-1.,0.,0.));
#653=DIRECTION('',(0.,0.,-1.));
#654=AXIS2_PLACEMENT_3D('',#651,#652,#653);
#655=CIRCLE('',#654,5.413375);
#656=CARTESIAN_POINT('',(1.72719999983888,5.36186305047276,-0.745019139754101));
#657=VERTEX_POINT('',#656);
#658=EDGE_CURVE('E474',#657,#648,#655,.T.);
#659=ORIENTED_EDGE('',*,*,#658,.F.);
#660=DIRECTION('',(0.,-1.,0.));
#661=VECTOR('',#660,1.);
#662=CARTESIAN_POINT('',(1.72719999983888,5.36186305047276,-0.745019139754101));
#663=LINE('',#662,#661);
#664=EDGE_CURVE('E456',#416,#657,#663,.T.);
#665=ORIENTED_EDGE('',*,*,#664,.F.);
#666=ORIENTED_EDGE('',*,*,#417,.F.);
#667=DIRECTION('',(0.,1.,0.));
#668=VECTOR('',#667,1.);
#669=CARTESIAN_POINT('',(1.72719999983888,5.36186305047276,0.745019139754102));
#670=LINE('',#669,#668);
#671=CARTESIAN_POINT('',(1.72719999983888,5.36186305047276,0.745019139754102));
#672=VERTEX_POINT('',#671);
#673=EDGE_CURVE('E891',#672,#410,#670,.T.);
#674=ORIENTED_EDGE('',*,*,#673,.F.);
#675=CARTESIAN_POINT('',(1.72719999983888,0.,0.));
#676=DIRECTION('',(-1.,0.,0.));
#677=DIRECTION('',(0.,0.707106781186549,-0.707106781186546));
#678=AXIS2_PLACEMENT_3D('',#675,#676,#677);
#679=CIRCLE('',#678,5.413375);
#680=CARTESIAN_POINT('',(1.72719999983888,4.31821780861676,3.26460163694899));
#681=VERTEX_POINT('',#680);
#682=EDGE_CURVE('E893',#681,#672,#679,.T.);
#683=ORIENTED_EDGE('',*,*,#682,.F.);
#684=DIRECTION('',(0.,-0.707106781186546,-0.707106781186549));
#685=VECTOR('',#684,1.);
#686=CARTESIAN_POINT('',(1.72719999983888,4.31821780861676,3.26460163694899));
#687=LINE('',#686,#685);
#688=EDGE_CURVE('E563',#43,#681,#687,.T.);
#689=ORIENTED_EDGE('',*,*,#688,.F.);
#690=ORIENTED_EDGE('',*,*,#44,.F.);
#691=EDGE_LOOP('',(#506,#515,#521,#522,#530,#539,#545,#546,#554,#563,#569,#570,#578,#587,#593,
#594,#602,#611,#617,#618,#626,#635,#641,#642,#650,#659,#665,#666,#674,#683,#689,#690));
#692=FACE_BOUND('',#691,.T.);
#693=CARTESIAN_POINT('',(1.7272,0.,0.));
#694=DIRECTION('',(-1.,0.,0.));
#695=DIRECTION('',(0.,0.,1.));
#696=AXIS2_PLACEMENT_3D('',#693,#694,#695);
#697=CIRCLE('',#696,4.7625);
#698=CARTESIAN_POINT('',(1.7272,0.,4.7625));
#699=VERTEX_POINT('',#698);
#700=EDGE_CURVE('E573',#699,#699,#697,.T.);
#701=ORIENTED_EDGE('',*,*,#700,.T.);
#702=EDGE_LOOP('',(#701));
#703=FACE_BOUND('',#702,.T.);
#704=ADVANCED_FACE('F533',(#692,#703),#498,.T.);
#705=CARTESIAN_POINT('',(0.,0.,0.));
#706=DIRECTION('',(-1.,0.,0.));
#707=DIRECTION('',(0.,0.,1.));
#708=AXIS2_PLACEMENT_3D('',#705,#706,#707);
#709=CYLINDRICAL_SURFACE('',#708,4.7625);
#710=CARTESIAN_POINT('',(24.4538499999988,0.,0.));
#711=DIRECTION('',(-1.,0.,0.));
#712=DIRECTION('',(0.,0.,1.));
#713=AXIS2_PLACEMENT_3D('',#710,#711,#712);
#714=CIRCLE('',#713,4.7625);
#715=CARTESIAN_POINT('',(24.4538499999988,0.,4.7625));
#716=VERTEX_POINT('',#715);
#717=EDGE_CURVE('E660',#716,#716,#714,.T.);
#718=ORIENTED_EDGE('',*,*,#717,.T.);
#719=EDGE_LOOP('',(#718));
#720=FACE_BOUND('',#719,.T.);
#721=ORIENTED_EDGE('',*,*,#700,.F.);
#722=EDGE_LOOP('',(#721));
#723=FACE_BOUND('',#722,.T.);
#724=ADVANCED_FACE('F535',(#720,#723),#709,.T.);
#725=CARTESIAN_POINT('',(25.4,0.,0.));
#726=DIRECTION('',(-1.,0.,0.));
#727=DIRECTION('',(0.,0.,1.));
#728=AXIS2_PLACEMENT_3D('',#725,#726,#727);
#729=CONICAL_SURFACE('',#728,3.81635,0.785398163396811);
#730=ORIENTED_EDGE('',*,*,#717,.F.);
#731=EDGE_LOOP('',(#730));
#732=FACE_BOUND('',#731,.T.);
#733=CARTESIAN_POINT('',(25.4,0.,0.));
#734=DIRECTION('',(-1.,0.,0.));
#735=DIRECTION('',(0.,0.,1.));
#736=AXIS2_PLACEMENT_3D('',#733,#734,#735);
#737=CIRCLE('',#736,3.81635);
#738=CARTESIAN_POINT('',(25.4,0.,3.81635));
#739=VERTEX_POINT('',#738);
#740=EDGE_CURVE('E652',#739,#739,#737,.T.);
#741=ORIENTED_EDGE('',*,*,#740,.T.);
#742=EDGE_LOOP('',(#741));
#743=FACE_BOUND('',#742,.T.);
#744=ADVANCED_FACE('F526',(#732,#743),#729,.T.);
#745=CARTESIAN_POINT('',(25.4,3.81635,0.));
#746=DIRECTION('',(1.,0.,0.));
#747=DIRECTION('',(0.,0.,-1.));
#748=AXIS2_PLACEMENT_3D('',#745,#746,#747);
#749=PLANE('',#748);
#750=ORIENTED_EDGE('',*,*,#740,.F.);
#751=EDGE_LOOP('',(#750));
#752=FACE_BOUND('',#751,.T.);
#753=ADVANCED_FACE('F522',(#752),#749,.T.);
#754=CARTESIAN_POINT('',(-2.159,6.9342,0.));
#755=DIRECTION('',(1.,0.,0.));
#756=DIRECTION('',(0.,0.,-1.));
#757=AXIS2_PLACEMENT_3D('',#754,#755,#756);
#758=PLANE('',#757);
#759=CARTESIAN_POINT('',(-2.159,0.,0.));
#760=DIRECTION('',(-1.,0.,0.));
#761=DIRECTION('',(0.,0.,1.));
#762=AXIS2_PLACEMENT_3D('',#759,#760,#761);
#763=CIRCLE('',#762,6.9342);
#764=CARTESIAN_POINT('',(-2.159,0.,6.9342));
#765=VERTEX_POINT('',#764);
#766=EDGE_CURVE('E653',#765,#765,#763,.T.);
#767=ORIENTED_EDGE('',*,*,#766,.T.);
#768=EDGE_LOOP('',(#767));
#769=FACE_BOUND('',#768,.T.);
#770=ADVANCED_FACE('F519',(#769),#758,.F.);
#771=CARTESIAN_POINT('',(-1.7272,0.,0.));
#772=DIRECTION('',(-1.,0.,0.));
#773=DIRECTION('',(0.,0.,1.));
#774=AXIS2_PLACEMENT_3D('',#771,#772,#773);
#775=TOROIDAL_SURFACE('',#774,6.9342,0.4318);
#776=CARTESIAN_POINT('',(-1.7272,0.,0.));
#777=DIRECTION('',(-1.,0.,0.));
#778=DIRECTION('',(0.,0.,1.));
#779=AXIS2_PLACEMENT_3D('',#776,#777,#778);
#780=CIRCLE('',#779,7.366);
#781=CARTESIAN_POINT('',(-1.7272,0.,7.366));
#782=VERTEX_POINT('',#781);
#783=EDGE_CURVE('E647',#782,#782,#780,.T.);
#784=ORIENTED_EDGE('',*,*,#783,.T.);
#785=EDGE_LOOP('',(#784));
#786=FACE_BOUND('',#785,.T.);
#787=ORIENTED_EDGE('',*,*,#766,.F.);
#788=EDGE_LOOP('',(#787));
#789=FACE_BOUND('',#788,.T.);
#790=ADVANCED_FACE('F516',(#786,#789),#775,.T.);
#791=CARTESIAN_POINT('',(0.,0.,0.));
#792=DIRECTION('',(-1.,0.,0.));
#793=DIRECTION('',(0.,0.,1.));
#794=AXIS2_PLACEMENT_3D('',#791,#792,#793);
#795=CYLINDRICAL_SURFACE('',#794,7.366);
#796=CARTESIAN_POINT('',(0.,0.,0.));
#797=DIRECTION('',(-1.,0.,0.));
#798=DIRECTION('',(0.,0.,1.));
#799=AXIS2_PLACEMENT_3D('',#796,#797,#798);
#800=CIRCLE('',#799,7.366);
#801=CARTESIAN_POINT('',(0.,0.,7.366));
#802=VERTEX_POINT('',#801);
#803=EDGE_CURVE('E644',#802,#802,#800,.T.);
#804=ORIENTED_EDGE('',*,*,#803,.T.);
#805=EDGE_LOOP('',(#804));
#806=FACE_BOUND('',#805,.T.);
#807=ORIENTED_EDGE('',*,*,#783,.F.);
#808=EDGE_LOOP('',(#807));
#809=FACE_BOUND('',#808,.T.);
#810=ADVANCED_FACE('F514',(#806,#809),#795,.T.);
#811=CARTESIAN_POINT('',(0.,7.36346,0.));
#812=DIRECTION('',(-1.,0.,0.));
#813=DIRECTION('',(0.,0.,1.));
#814=AXIS2_PLACEMENT_3D('',#811,#812,#813);
#815=PLANE('',#814);
#816=DIRECTION('',(0.,0.707106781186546,0.707106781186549));
#817=VECTOR('',#816,1.);
#818=CARTESIAN_POINT('',(-1.61121766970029E-10,3.26460163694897,4.31821780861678));
#819=LINE('',#818,#817);
#820=CARTESIAN_POINT('',(-1.61121766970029E-10,3.26460163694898,4.31821780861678));
#821=VERTEX_POINT('',#820);
#822=EDGE_CURVE('E54',#821,#267,#819,.T.);
#823=ORIENTED_EDGE('',*,*,#822,.T.);
#824=ORIENTED_EDGE('',*,*,#270,.T.);
#825=DIRECTION('',(0.,-0.707106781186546,-0.707106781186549));
#826=VECTOR('',#825,1.);
#827=CARTESIAN_POINT('',(-1.61121766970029E-10,4.31821780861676,3.26460163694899));
#828=LINE('',#827,#826);
#829=CARTESIAN_POINT('',(-1.61121766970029E-10,4.31821780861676,3.26460163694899));
#830=VERTEX_POINT('',#829);
#831=EDGE_CURVE('E885',#269,#830,#828,.T.);
#832=ORIENTED_EDGE('',*,*,#831,.T.);
#833=CARTESIAN_POINT('',(-1.61121766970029E-10,0.,0.));
#834=DIRECTION('',(-1.,0.,0.));
#835=DIRECTION('',(0.,0.707106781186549,-0.707106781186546));
#836=AXIS2_PLACEMENT_3D('',#833,#834,#835);
#837=CIRCLE('',#836,5.413375);
#838=CARTESIAN_POINT('',(-1.61121766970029E-10,5.36186305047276,0.745019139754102));
#839=VERTEX_POINT('',#838);
#840=EDGE_CURVE('E900',#830,#839,#837,.T.);
#841=ORIENTED_EDGE('',*,*,#840,.T.);
#842=DIRECTION('',(0.,1.,0.));
#843=VECTOR('',#842,1.);
#844=CARTESIAN_POINT('',(-1.61121766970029E-10,5.36186305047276,0.745019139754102));
#845=LINE('',#844,#843);
#846=EDGE_CURVE('E887',#839,#440,#845,.T.);
#847=ORIENTED_EDGE('',*,*,#846,.T.);
#848=ORIENTED_EDGE('',*,*,#443,.T.);
#849=DIRECTION('',(0.,-1.,0.));
#850=VECTOR('',#849,1.);
#851=CARTESIAN_POINT('',(-1.61121766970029E-10,5.36186305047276,-0.745019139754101));
#852=LINE('',#851,#850);
#853=CARTESIAN_POINT('',(-1.61121766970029E-10,5.36186305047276,-0.745019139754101));
#854=VERTEX_POINT('',#853);
#855=EDGE_CURVE('E464',#442,#854,#852,.T.);
#856=ORIENTED_EDGE('',*,*,#855,.T.);
#857=CARTESIAN_POINT('',(-1.61121766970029E-10,0.,0.));
#858=DIRECTION('',(-1.,0.,0.));
#859=DIRECTION('',(0.,0.,-1.));
#860=AXIS2_PLACEMENT_3D('',#857,#858,#859);
#861=CIRCLE('',#860,5.413375);
#862=CARTESIAN_POINT('',(-1.61121766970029E-10,4.31821780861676,-3.26460163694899));
#863=VERTEX_POINT('',#862);
#864=EDGE_CURVE('E470',#854,#863,#861,.T.);
#865=ORIENTED_EDGE('',*,*,#864,.T.);
#866=DIRECTION('',(0.,0.707106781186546,-0.707106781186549));
#867=VECTOR('',#866,1.);
#868=CARTESIAN_POINT('',(-1.61121766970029E-10,4.31821780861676,-3.26460163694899));
#869=LINE('',#868,#867);
#870=CARTESIAN_POINT('',(0.,5.70684137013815,-4.65322519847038));
#871=VERTEX_POINT('',#870);
#872=EDGE_CURVE('E471',#863,#871,#869,.T.);
#873=ORIENTED_EDGE('',*,*,#872,.T.);
#874=CARTESIAN_POINT('',(-1.61121766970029E-10,4.65322519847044,-5.7068413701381));
#875=VERTEX_POINT('',#874);
#876=EDGE_CURVE('E639',#871,#875,#265,.T.);
#877=ORIENTED_EDGE('',*,*,#876,.T.);
#878=DIRECTION('',(0.,-0.707106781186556,0.707106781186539));
#879=VECTOR('',#878,1.);
#880=CARTESIAN_POINT('',(-1.61121766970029E-10,3.26460163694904,-4.31821780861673));
#881=LINE('',#880,#879);
#882=CARTESIAN_POINT('',(-1.61121766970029E-10,3.26460163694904,-4.31821780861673));
#883=VERTEX_POINT('',#882);
#884=EDGE_CURVE('E386',#875,#883,#881,.T.);
#885=ORIENTED_EDGE('',*,*,#884,.T.);
#886=CARTESIAN_POINT('',(-1.61121766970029E-10,0.,0.));
#887=DIRECTION('',(-1.,0.,0.));
#888=DIRECTION('',(0.,-0.707106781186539,-0.707106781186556));
#889=AXIS2_PLACEMENT_3D('',#886,#887,#888);
#890=CIRCLE('',#889,5.413375);
#891=CARTESIAN_POINT('',(-1.61121766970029E-10,0.745019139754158,-5.36186305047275));
#892=VERTEX_POINT('',#891);
#893=EDGE_CURVE('E387',#883,#892,#890,.T.);
#894=ORIENTED_EDGE('',*,*,#893,.T.);
#895=DIRECTION('',(0.,0.,-1.));
#896=VECTOR('',#895,1.);
#897=CARTESIAN_POINT('',(-1.61121766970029E-10,0.745019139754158,-5.36186305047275));
#898=LINE('',#897,#896);
#899=EDGE_CURVE('E395',#892,#333,#898,.T.);
#900=ORIENTED_EDGE('',*,*,#899,.T.);
#901=ORIENTED_EDGE('',*,*,#336,.T.);
#902=DIRECTION('',(0.,0.,1.));
#903=VECTOR('',#902,1.);
#904=CARTESIAN_POINT('',(-1.61121766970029E-10,-0.745019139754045,-5.36186305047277));
#905=LINE('',#904,#903);
#906=CARTESIAN_POINT('',(-1.61121766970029E-10,-0.745019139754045,-5.36186305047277));
#907=VERTEX_POINT('',#906);
#908=EDGE_CURVE('E362',#335,#907,#905,.T.);
#909=ORIENTED_EDGE('',*,*,#908,.T.);
#910=CARTESIAN_POINT('',(-1.61121766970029E-10,0.,0.));
#911=DIRECTION('',(-1.,0.,0.));
#912=DIRECTION('',(0.,-1.,0.));
#913=AXIS2_PLACEMENT_3D('',#910,#911,#912);
#914=CIRCLE('',#913,5.413375);
#915=CARTESIAN_POINT('',(-1.61121766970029E-10,-3.26460163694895,-4.3182178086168));
#916=VERTEX_POINT('',#915);
#917=EDGE_CURVE('E370',#907,#916,#914,.T.);
#918=ORIENTED_EDGE('',*,*,#917,.T.);
#919=DIRECTION('',(0.,-0.707106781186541,-0.707106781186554));
#920=VECTOR('',#919,1.);
#921=CARTESIAN_POINT('',(-1.61121766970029E-10,-3.26460163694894,-4.3182178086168));
#922=LINE('',#921,#920);
#923=EDGE_CURVE('E371',#916,#355,#922,.T.);
#924=ORIENTED_EDGE('',*,*,#923,.T.);
#925=ORIENTED_EDGE('',*,*,#358,.T.);
#926=DIRECTION('',(0.,0.707106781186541,0.707106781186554));
#927=VECTOR('',#926,1.);
#928=CARTESIAN_POINT('',(-1.61121766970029E-10,-4.31821780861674,-3.26460163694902));
#929=LINE('',#928,#927);
#930=CARTESIAN_POINT('',(-1.61121766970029E-10,-4.31821780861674,-3.26460163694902));
#931=VERTEX_POINT('',#930);
#932=EDGE_CURVE('E404',#357,#931,#929,.T.);
#933=ORIENTED_EDGE('',*,*,#932,.T.);
#934=CARTESIAN_POINT('',(-1.61121766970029E-10,0.,0.));
#935=DIRECTION('',(-1.,0.,0.));
#936=DIRECTION('',(0.,-0.707106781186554,0.707106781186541));
#937=AXIS2_PLACEMENT_3D('',#934,#935,#936);
#938=CIRCLE('',#937,5.413375);
#939=CARTESIAN_POINT('',(-1.61121766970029E-10,-5.36186305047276,-0.74501913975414));
#940=VERTEX_POINT('',#939);
#941=EDGE_CURVE('E406',#931,#940,#938,.T.);
#942=ORIENTED_EDGE('',*,*,#941,.T.);
#943=DIRECTION('',(0.,-1.,0.));
#944=VECTOR('',#943,1.);
#945=CARTESIAN_POINT('',(-1.61121766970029E-10,-5.36186305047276,-0.74501913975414));
#946=LINE('',#945,#944);
#947=EDGE_CURVE('E409',#940,#386,#946,.T.);
#948=ORIENTED_EDGE('',*,*,#947,.T.);
#949=ORIENTED_EDGE('',*,*,#387,.T.);
#950=DIRECTION('',(0.,1.,0.));
#951=VECTOR('',#950,1.);
#952=CARTESIAN_POINT('',(-1.61121766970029E-10,-5.36186305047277,0.745019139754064));
#953=LINE('',#952,#951);
#954=CARTESIAN_POINT('',(-1.61121766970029E-10,-5.36186305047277,0.745019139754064));
#955=VERTEX_POINT('',#954);
#956=EDGE_CURVE('E327',#382,#955,#953,.T.);
#957=ORIENTED_EDGE('',*,*,#956,.T.);
#958=CARTESIAN_POINT('',(-1.61121766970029E-10,0.,0.));
#959=DIRECTION('',(-1.,0.,0.));
#960=DIRECTION('',(0.,0.,1.));
#961=AXIS2_PLACEMENT_3D('',#958,#959,#960);
#962=CIRCLE('',#961,5.413375);
#963=CARTESIAN_POINT('',(-1.61121766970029E-10,-4.31821780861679,3.26460163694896));
#964=VERTEX_POINT('',#963);
#965=EDGE_CURVE('E333',#955,#964,#962,.T.);
#966=ORIENTED_EDGE('',*,*,#965,.T.);
#967=DIRECTION('',(0.,-0.707106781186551,0.707106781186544));
#968=VECTOR('',#967,1.);
#969=CARTESIAN_POINT('',(-1.61121766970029E-10,-4.31821780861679,3.26460163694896));
#970=LINE('',#969,#968);
#971=EDGE_CURVE('E334',#964,#289,#970,.T.);
#972=ORIENTED_EDGE('',*,*,#971,.T.);
#973=ORIENTED_EDGE('',*,*,#292,.T.);
#974=DIRECTION('',(0.,0.707106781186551,-0.707106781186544));
#975=VECTOR('',#974,1.);
#976=CARTESIAN_POINT('',(-1.61121766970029E-10,-3.26460163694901,4.31821780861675));
#977=LINE('',#976,#975);
#978=CARTESIAN_POINT('',(-1.61121766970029E-10,-3.26460163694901,4.31821780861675));
#979=VERTEX_POINT('',#978);
#980=EDGE_CURVE('E349',#291,#979,#977,.T.);
#981=ORIENTED_EDGE('',*,*,#980,.T.);
#982=CARTESIAN_POINT('',(-1.61121766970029E-10,0.,0.));
#983=DIRECTION('',(-1.,0.,0.));
#984=DIRECTION('',(0.,0.707106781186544,0.707106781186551));
#985=AXIS2_PLACEMENT_3D('',#982,#983,#984);
#986=CIRCLE('',#985,5.413375);
#987=CARTESIAN_POINT('',(-1.61121766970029E-10,-0.745019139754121,5.36186305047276));
#988=VERTEX_POINT('',#987);
#989=EDGE_CURVE('E355',#979,#988,#986,.T.);
#990=ORIENTED_EDGE('',*,*,#989,.T.);
#991=DIRECTION('',(0.,0.,1.));
#992=VECTOR('',#991,1.);
#993=CARTESIAN_POINT('',(-1.61121766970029E-10,-0.745019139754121,5.36186305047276));
#994=LINE('',#993,#992);
#995=EDGE_CURVE('E65',#988,#320,#994,.T.);
#996=ORIENTED_EDGE('',*,*,#995,.T.);
#997=ORIENTED_EDGE('',*,*,#321,.T.);
#998=DIRECTION('',(0.,0.,-1.));
#999=VECTOR('',#998,1.);
#1000=CARTESIAN_POINT('',(-1.61121766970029E-10,0.745019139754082,5.36186305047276));
#1001=LINE('',#1000,#999);
#1002=CARTESIAN_POINT('',(-1.61121766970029E-10,0.745019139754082,5.36186305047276));
#1003=VERTEX_POINT('',#1002);
#1004=EDGE_CURVE('E298',#316,#1003,#1001,.T.);
#1005=ORIENTED_EDGE('',*,*,#1004,.T.);
#1006=CARTESIAN_POINT('',(-1.61121766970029E-10,0.,0.));
#1007=DIRECTION('',(-1.,0.,0.));
#1008=DIRECTION('',(0.,1.,0.));
#1009=AXIS2_PLACEMENT_3D('',#1006,#1007,#1008);
#1010=CIRCLE('',#1009,5.413375);
#1011=EDGE_CURVE('E301',#1003,#821,#1010,.T.);
#1012=ORIENTED_EDGE('',*,*,#1011,.T.);
#1013=EDGE_LOOP('',(#823,#824,#832,#841,#847,#848,#856,#865,#873,#877,#885,#894,#900,#901,#909,
#918,#924,#925,#933,#942,#948,#949,#957,#966,#972,#973,#981,#990,#996,#997,#1005,#1012));
#1014=FACE_BOUND('',#1013,.T.);
#1015=ORIENTED_EDGE('',*,*,#803,.F.);
#1016=EDGE_LOOP('',(#1015));
#1017=FACE_BOUND('',#1016,.T.);
#1018=ADVANCED_FACE('F296',(#1014,#1017),#815,.F.);
#1019=ORIENTED_EDGE('',*,*,#476,.T.);
#1020=DIRECTION('',(-1.,0.,0.));
#1021=VECTOR('',#1020,1.);
#1022=CARTESIAN_POINT('',(0.,4.65322519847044,-5.7068413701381));
#1023=LINE('',#1022,#1021);
#1024=EDGE_CURVE('E864',#469,#875,#1023,.T.);
#1025=ORIENTED_EDGE('',*,*,#1024,.T.);
#1026=ORIENTED_EDGE('',*,*,#876,.F.);
#1027=DIRECTION('',(-1.,0.,0.));
#1028=VECTOR('',#1027,1.);
#1029=CARTESIAN_POINT('',(0.,5.70684137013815,-4.65322519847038));
#1030=LINE('',#1029,#1028);
#1031=EDGE_CURVE('E583',#871,#475,#1030,.F.);
#1032=ORIENTED_EDGE('',*,*,#1031,.T.);
#1033=EDGE_LOOP('',(#1019,#1025,#1026,#1032));
#1034=FACE_BOUND('',#1033,.T.);
#1035=ADVANCED_FACE('F502',(#1034),#260,.T.);
#1036=CARTESIAN_POINT('',(-1.61121766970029E-10,4.31821780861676,-3.26460163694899));
#1037=DIRECTION('',(0.,-0.707106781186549,-0.707106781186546));
#1038=DIRECTION('',(0.,0.707106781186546,-0.707106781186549));
#1039=AXIS2_PLACEMENT_3D('',#1036,#1037,#1038);
#1040=PLANE('',#1039);
#1041=ORIENTED_EDGE('',*,*,#487,.T.);
#1042=ORIENTED_EDGE('',*,*,#1031,.F.);
#1043=ORIENTED_EDGE('',*,*,#872,.F.);
#1044=DIRECTION('',(1.,0.,0.));
#1045=VECTOR('',#1044,1.);
#1046=CARTESIAN_POINT('',(-1.61121766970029E-10,4.31821780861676,-3.26460163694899));
#1047=LINE('',#1046,#1045);
#1048=EDGE_CURVE('E477',#863,#648,#1047,.T.);
#1049=ORIENTED_EDGE('',*,*,#1048,.T.);
#1050=ORIENTED_EDGE('',*,*,#649,.T.);
#1051=EDGE_LOOP('',(#1041,#1042,#1043,#1049,#1050));
#1052=FACE_BOUND('',#1051,.T.);
#1053=ADVANCED_FACE('F510',(#1052),#1040,.F.);
#1054=CARTESIAN_POINT('',(-1.61121766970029E-10,0.,0.));
#1055=DIRECTION('',(1.,0.,0.));
#1056=DIRECTION('',(0.,0.,-1.));
#1057=AXIS2_PLACEMENT_3D('',#1054,#1055,#1056);
#1058=CYLINDRICAL_SURFACE('',#1057,5.413375);
#1059=ORIENTED_EDGE('',*,*,#658,.T.);
#1060=ORIENTED_EDGE('',*,*,#1048,.F.);
#1061=ORIENTED_EDGE('',*,*,#864,.F.);
#1062=DIRECTION('',(1.,0.,0.));
#1063=VECTOR('',#1062,1.);
#1064=CARTESIAN_POINT('',(-1.61121766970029E-10,5.36186305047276,-0.745019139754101));
#1065=LINE('',#1064,#1063);
#1066=EDGE_CURVE('E472',#854,#657,#1065,.T.);
#1067=ORIENTED_EDGE('',*,*,#1066,.T.);
#1068=EDGE_LOOP('',(#1059,#1060,#1061,#1067));
#1069=FACE_BOUND('',#1068,.T.);
#1070=ADVANCED_FACE('F505',(#1069),#1058,.T.);
#1071=CARTESIAN_POINT('',(-1.61121766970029E-10,5.36186305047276,-0.745019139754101));
#1072=DIRECTION('',(0.,0.,1.));
#1073=DIRECTION('',(1.,0.,0.));
#1074=AXIS2_PLACEMENT_3D('',#1071,#1072,#1073);
#1075=PLANE('',#1074);
#1076=ORIENTED_EDGE('',*,*,#432,.T.);
#1077=ORIENTED_EDGE('',*,*,#664,.T.);
#1078=ORIENTED_EDGE('',*,*,#1066,.F.);
#1079=ORIENTED_EDGE('',*,*,#855,.F.);
#1080=ORIENTED_EDGE('',*,*,#456,.F.);
#1081=EDGE_LOOP('',(#1076,#1077,#1078,#1079,#1080));
#1082=FACE_BOUND('',#1081,.T.);
#1083=ADVANCED_FACE('F450',(#1082),#1075,.F.);
#1084=CARTESIAN_POINT('',(-1.61121766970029E-10,5.36186305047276,0.745019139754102));
#1085=DIRECTION('',(0.,0.,-1.));
#1086=DIRECTION('',(0.,1.,0.));
#1087=AXIS2_PLACEMENT_3D('',#1084,#1085,#1086);
#1088=PLANE('',#1087);
#1089=ORIENTED_EDGE('',*,*,#413,.T.);
#1090=ORIENTED_EDGE('',*,*,#449,.F.);
#1091=ORIENTED_EDGE('',*,*,#846,.F.);
#1092=DIRECTION('',(1.,0.,0.));
#1093=VECTOR('',#1092,1.);
#1094=CARTESIAN_POINT('',(-1.61121766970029E-10,5.36186305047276,0.745019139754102));
#1095=LINE('',#1094,#1093);
#1096=EDGE_CURVE('E881',#839,#672,#1095,.T.);
#1097=ORIENTED_EDGE('',*,*,#1096,.T.);
#1098=ORIENTED_EDGE('',*,*,#673,.T.);
#1099=EDGE_LOOP('',(#1089,#1090,#1091,#1097,#1098));
#1100=FACE_BOUND('',#1099,.T.);
#1101=ADVANCED_FACE('F445',(#1100),#1088,.F.);
#1102=CARTESIAN_POINT('',(-1.61121766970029E-10,0.,0.));
#1103=DIRECTION('',(1.,0.,0.));
#1104=DIRECTION('',(0.,0.,-1.));
#1105=AXIS2_PLACEMENT_3D('',#1102,#1103,#1104);
#1106=CYLINDRICAL_SURFACE('',#1105,5.413375);
#1107=ORIENTED_EDGE('',*,*,#682,.T.);
#1108=ORIENTED_EDGE('',*,*,#1096,.F.);
#1109=ORIENTED_EDGE('',*,*,#840,.F.);
#1110=DIRECTION('',(1.,0.,0.));
#1111=VECTOR('',#1110,1.);
#1112=CARTESIAN_POINT('',(-1.61121766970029E-10,4.31821780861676,3.26460163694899));
#1113=LINE('',#1112,#1111);
#1114=EDGE_CURVE('E884',#830,#681,#1113,.T.);
#1115=ORIENTED_EDGE('',*,*,#1114,.T.);
#1116=EDGE_LOOP('',(#1107,#1108,#1109,#1115));
#1117=FACE_BOUND('',#1116,.T.);
#1118=ADVANCED_FACE('F447',(#1117),#1106,.T.);
#1119=CARTESIAN_POINT('',(-1.61121766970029E-10,4.31821780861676,3.26460163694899));
#1120=DIRECTION('',(0.,-0.707106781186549,0.707106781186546));
#1121=DIRECTION('',(0.,-0.707106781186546,-0.707106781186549));
#1122=AXIS2_PLACEMENT_3D('',#1119,#1120,#1121);
#1123=PLANE('',#1122);
#1124=ORIENTED_EDGE('',*,*,#55,.T.);
#1125=ORIENTED_EDGE('',*,*,#688,.T.);
#1126=ORIENTED_EDGE('',*,*,#1114,.F.);
#1127=ORIENTED_EDGE('',*,*,#831,.F.);
#1128=ORIENTED_EDGE('',*,*,#283,.F.);
#1129=EDGE_LOOP('',(#1124,#1125,#1126,#1127,#1128));
#1130=FACE_BOUND('',#1129,.T.);
#1131=ADVANCED_FACE('F721',(#1130),#1123,.F.);
#1132=CARTESIAN_POINT('',(-1.61121766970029E-10,-5.36186305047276,-0.74501913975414));
#1133=DIRECTION('',(0.,0.,1.));
#1134=DIRECTION('',(0.,-1.,0.));
#1135=AXIS2_PLACEMENT_3D('',#1132,#1133,#1134);
#1136=PLANE('',#1135);
#1137=ORIENTED_EDGE('',*,*,#249,.T.);
#1138=ORIENTED_EDGE('',*,*,#393,.F.);
#1139=ORIENTED_EDGE('',*,*,#947,.F.);
#1140=DIRECTION('',(1.,0.,0.));
#1141=VECTOR('',#1140,1.);
#1142=CARTESIAN_POINT('',(-1.61121766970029E-10,-5.36186305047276,-0.74501913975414));
#1143=LINE('',#1142,#1141);
#1144=EDGE_CURVE('E341',#940,#576,#1143,.T.);
#1145=ORIENTED_EDGE('',*,*,#1144,.T.);
#1146=ORIENTED_EDGE('',*,*,#577,.T.);
#1147=EDGE_LOOP('',(#1137,#1138,#1139,#1145,#1146));
#1148=FACE_BOUND('',#1147,.T.);
#1149=ADVANCED_FACE('F719',(#1148),#1136,.F.);
#1150=CARTESIAN_POINT('',(-1.61121766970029E-10,0.,0.));
#1151=DIRECTION('',(1.,0.,0.));
#1152=DIRECTION('',(0.,0.,-1.));
#1153=AXIS2_PLACEMENT_3D('',#1150,#1151,#1152);
#1154=CYLINDRICAL_SURFACE('',#1153,5.413375);
#1155=ORIENTED_EDGE('',*,*,#586,.T.);
#1156=ORIENTED_EDGE('',*,*,#1144,.F.);
#1157=ORIENTED_EDGE('',*,*,#941,.F.);
#1158=DIRECTION('',(1.,0.,0.));
#1159=VECTOR('',#1158,1.);
#1160=CARTESIAN_POINT('',(-1.61121766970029E-10,-4.31821780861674,-3.26460163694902));
#1161=LINE('',#1160,#1159);
#1162=EDGE_CURVE('E415',#931,#585,#1161,.T.);
#1163=ORIENTED_EDGE('',*,*,#1162,.T.);
#1164=EDGE_LOOP('',(#1155,#1156,#1157,#1163));
#1165=FACE_BOUND('',#1164,.T.);
#1166=ADVANCED_FACE('F439',(#1165),#1154,.T.);
#1167=CARTESIAN_POINT('',(-1.61121766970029E-10,-4.31821780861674,-3.26460163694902));
#1168=DIRECTION('',(0.,0.707106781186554,-0.707106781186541));
#1169=DIRECTION('',(0.,0.707106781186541,0.707106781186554));
#1170=AXIS2_PLACEMENT_3D('',#1167,#1168,#1169);
#1171=PLANE('',#1170);
#1172=ORIENTED_EDGE('',*,*,#208,.T.);
#1173=ORIENTED_EDGE('',*,*,#592,.T.);
#1174=ORIENTED_EDGE('',*,*,#1162,.F.);
#1175=ORIENTED_EDGE('',*,*,#932,.F.);
#1176=ORIENTED_EDGE('',*,*,#371,.F.);
#1177=EDGE_LOOP('',(#1172,#1173,#1174,#1175,#1176));
#1178=FACE_BOUND('',#1177,.T.);
#1179=ADVANCED_FACE('F432',(#1178),#1171,.F.);
#1180=CARTESIAN_POINT('',(-1.61121766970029E-10,-3.26460163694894,-4.3182178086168));
#1181=DIRECTION('',(0.,-0.707106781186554,0.707106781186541));
#1182=DIRECTION('',(0.,-0.707106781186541,-0.707106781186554));
#1183=AXIS2_PLACEMENT_3D('',#1180,#1181,#1182);
#1184=PLANE('',#1183);
#1185=ORIENTED_EDGE('',*,*,#193,.T.);
#1186=ORIENTED_EDGE('',*,*,#364,.F.);
#1187=ORIENTED_EDGE('',*,*,#923,.F.);
#1188=DIRECTION('',(1.,0.,0.));
#1189=VECTOR('',#1188,1.);
#1190=CARTESIAN_POINT('',(-1.61121766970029E-10,-3.26460163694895,-4.3182178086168));
#1191=LINE('',#1190,#1189);
#1192=EDGE_CURVE('E382',#916,#600,#1191,.T.);
#1193=ORIENTED_EDGE('',*,*,#1192,.T.);
#1194=ORIENTED_EDGE('',*,*,#601,.T.);
#1195=EDGE_LOOP('',(#1185,#1186,#1187,#1193,#1194));
#1196=FACE_BOUND('',#1195,.T.);
#1197=ADVANCED_FACE('F437',(#1196),#1184,.F.);
#1198=CARTESIAN_POINT('',(-1.61121766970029E-10,0.,0.));
#1199=DIRECTION('',(1.,0.,0.));
#1200=DIRECTION('',(0.,0.,-1.));
#1201=AXIS2_PLACEMENT_3D('',#1198,#1199,#1200);
#1202=CYLINDRICAL_SURFACE('',#1201,5.413375);
#1203=ORIENTED_EDGE('',*,*,#610,.T.);
#1204=ORIENTED_EDGE('',*,*,#1192,.F.);
#1205=ORIENTED_EDGE('',*,*,#917,.F.);
#1206=DIRECTION('',(1.,0.,0.));
#1207=VECTOR('',#1206,1.);
#1208=CARTESIAN_POINT('',(-1.61121766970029E-10,-0.745019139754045,-5.36186305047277));
#1209=LINE('',#1208,#1207);
#1210=EDGE_CURVE('E373',#907,#609,#1209,.T.);
#1211=ORIENTED_EDGE('',*,*,#1210,.T.);
#1212=EDGE_LOOP('',(#1203,#1204,#1205,#1211));
#1213=FACE_BOUND('',#1212,.T.);
#1214=ADVANCED_FACE('F814',(#1213),#1202,.T.);
#1215=CARTESIAN_POINT('',(-1.61121766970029E-10,-0.745019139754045,-5.36186305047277));
#1216=DIRECTION('',(0.,1.,0.));
#1217=DIRECTION('',(0.,0.,1.));
#1218=AXIS2_PLACEMENT_3D('',#1215,#1216,#1217);
#1219=PLANE('',#1218);
#1220=ORIENTED_EDGE('',*,*,#175,.T.);
#1221=ORIENTED_EDGE('',*,*,#616,.T.);
#1222=ORIENTED_EDGE('',*,*,#1210,.F.);
#1223=ORIENTED_EDGE('',*,*,#908,.F.);
#1224=ORIENTED_EDGE('',*,*,#349,.F.);
#1225=EDGE_LOOP('',(#1220,#1221,#1222,#1223,#1224));
#1226=FACE_BOUND('',#1225,.T.);
#1227=ADVANCED_FACE('F819',(#1226),#1219,.F.);
#1228=CARTESIAN_POINT('',(-1.61121766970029E-10,0.745019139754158,-5.36186305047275));
#1229=DIRECTION('',(0.,-1.,0.));
#1230=DIRECTION('',(0.,0.,-1.));
#1231=AXIS2_PLACEMENT_3D('',#1228,#1229,#1230);
#1232=PLANE('',#1231);
#1233=ORIENTED_EDGE('',*,*,#156,.T.);
#1234=ORIENTED_EDGE('',*,*,#342,.F.);
#1235=ORIENTED_EDGE('',*,*,#899,.F.);
#1236=DIRECTION('',(1.,0.,0.));
#1237=VECTOR('',#1236,1.);
#1238=CARTESIAN_POINT('',(-1.61121766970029E-10,0.745019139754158,-5.36186305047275));
#1239=LINE('',#1238,#1237);
#1240=EDGE_CURVE('E380',#892,#624,#1239,.T.);
#1241=ORIENTED_EDGE('',*,*,#1240,.T.);
#1242=ORIENTED_EDGE('',*,*,#625,.T.);
#1243=EDGE_LOOP('',(#1233,#1234,#1235,#1241,#1242));
#1244=FACE_BOUND('',#1243,.T.);
#1245=ADVANCED_FACE('F823',(#1244),#1232,.F.);
#1246=CARTESIAN_POINT('',(-1.61121766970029E-10,0.,0.));
#1247=DIRECTION('',(1.,0.,0.));
#1248=DIRECTION('',(0.,0.,-1.));
#1249=AXIS2_PLACEMENT_3D('',#1246,#1247,#1248);
#1250=CYLINDRICAL_SURFACE('',#1249,5.413375);
#1251=ORIENTED_EDGE('',*,*,#634,.T.);
#1252=ORIENTED_EDGE('',*,*,#1240,.F.);
#1253=ORIENTED_EDGE('',*,*,#893,.F.);
#1254=DIRECTION('',(1.,0.,0.));
#1255=VECTOR('',#1254,1.);
#1256=CARTESIAN_POINT('',(-1.61121766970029E-10,3.26460163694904,-4.31821780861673));
#1257=LINE('',#1256,#1255);
#1258=EDGE_CURVE('E392',#883,#633,#1257,.T.);
#1259=ORIENTED_EDGE('',*,*,#1258,.T.);
#1260=EDGE_LOOP('',(#1251,#1252,#1253,#1259));
#1261=FACE_BOUND('',#1260,.T.);
#1262=ADVANCED_FACE('F717',(#1261),#1250,.T.);
#1263=CARTESIAN_POINT('',(-1.61121766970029E-10,3.26460163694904,-4.31821780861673));
#1264=DIRECTION('',(0.,0.707106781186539,0.707106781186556));
#1265=DIRECTION('',(0.,-0.707106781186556,0.707106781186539));
#1266=AXIS2_PLACEMENT_3D('',#1263,#1264,#1265);
#1267=PLANE('',#1266);
#1268=ORIENTED_EDGE('',*,*,#472,.T.);
#1269=ORIENTED_EDGE('',*,*,#640,.T.);
#1270=ORIENTED_EDGE('',*,*,#1258,.F.);
#1271=ORIENTED_EDGE('',*,*,#884,.F.);
#1272=ORIENTED_EDGE('',*,*,#1024,.F.);
#1273=EDGE_LOOP('',(#1268,#1269,#1270,#1271,#1272));
#1274=FACE_BOUND('',#1273,.T.);
#1275=ADVANCED_FACE('F714',(#1274),#1267,.F.);
#1276=CARTESIAN_POINT('',(-1.61121766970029E-10,-0.745019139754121,5.36186305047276));
#1277=DIRECTION('',(0.,1.,0.));
#1278=DIRECTION('',(0.,0.,1.));
#1279=AXIS2_PLACEMENT_3D('',#1276,#1277,#1278);
#1280=PLANE('',#1279);
#1281=ORIENTED_EDGE('',*,*,#134,.T.);
#1282=ORIENTED_EDGE('',*,*,#327,.F.);
#1283=ORIENTED_EDGE('',*,*,#995,.F.);
#1284=DIRECTION('',(1.,0.,0.));
#1285=VECTOR('',#1284,1.);
#1286=CARTESIAN_POINT('',(-1.61121766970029E-10,-0.745019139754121,5.36186305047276));
#1287=LINE('',#1286,#1285);
#1288=EDGE_CURVE('E323',#988,#528,#1287,.T.);
#1289=ORIENTED_EDGE('',*,*,#1288,.T.);
#1290=ORIENTED_EDGE('',*,*,#529,.T.);
#1291=EDGE_LOOP('',(#1281,#1282,#1283,#1289,#1290));
#1292=FACE_BOUND('',#1291,.T.);
#1293=ADVANCED_FACE('F621',(#1292),#1280,.F.);
#1294=CARTESIAN_POINT('',(-1.61121766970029E-10,0.,0.));
#1295=DIRECTION('',(1.,0.,0.));
#1296=DIRECTION('',(0.,0.,-1.));
#1297=AXIS2_PLACEMENT_3D('',#1294,#1295,#1296);
#1298=CYLINDRICAL_SURFACE('',#1297,5.413375);
#1299=ORIENTED_EDGE('',*,*,#538,.T.);
#1300=ORIENTED_EDGE('',*,*,#1288,.F.);
#1301=ORIENTED_EDGE('',*,*,#989,.F.);
#1302=DIRECTION('',(1.,0.,0.));
#1303=VECTOR('',#1302,1.);
#1304=CARTESIAN_POINT('',(-1.61121766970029E-10,-3.26460163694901,4.31821780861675));
#1305=LINE('',#1304,#1303);
#1306=EDGE_CURVE('E358',#979,#537,#1305,.T.);
#1307=ORIENTED_EDGE('',*,*,#1306,.T.);
#1308=EDGE_LOOP('',(#1299,#1300,#1301,#1307));
#1309=FACE_BOUND('',#1308,.T.);
#1310=ADVANCED_FACE('F619',(#1309),#1298,.T.);
#1311=CARTESIAN_POINT('',(-1.61121766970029E-10,-3.26460163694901,4.31821780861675));
#1312=DIRECTION('',(0.,-0.707106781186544,-0.707106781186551));
#1313=DIRECTION('',(0.,0.707106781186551,-0.707106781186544));
#1314=AXIS2_PLACEMENT_3D('',#1311,#1312,#1313);
#1315=PLANE('',#1314);
#1316=ORIENTED_EDGE('',*,*,#93,.T.);
#1317=ORIENTED_EDGE('',*,*,#544,.T.);
#1318=ORIENTED_EDGE('',*,*,#1306,.F.);
#1319=ORIENTED_EDGE('',*,*,#980,.F.);
#1320=ORIENTED_EDGE('',*,*,#305,.F.);
#1321=EDGE_LOOP('',(#1316,#1317,#1318,#1319,#1320));
#1322=FACE_BOUND('',#1321,.T.);
#1323=ADVANCED_FACE('F617',(#1322),#1315,.F.);
#1324=CARTESIAN_POINT('',(-1.61121766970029E-10,-4.31821780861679,3.26460163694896));
#1325=DIRECTION('',(0.,0.707106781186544,0.707106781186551));
#1326=DIRECTION('',(0.,-0.707106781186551,0.707106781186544));
#1327=AXIS2_PLACEMENT_3D('',#1324,#1325,#1326);
#1328=PLANE('',#1327);
#1329=ORIENTED_EDGE('',*,*,#78,.T.);
#1330=ORIENTED_EDGE('',*,*,#298,.F.);
#1331=ORIENTED_EDGE('',*,*,#971,.F.);
#1332=DIRECTION('',(1.,0.,0.));
#1333=VECTOR('',#1332,1.);
#1334=CARTESIAN_POINT('',(-1.61121766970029E-10,-4.31821780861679,3.26460163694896));
#1335=LINE('',#1334,#1333);
#1336=EDGE_CURVE('E344',#964,#552,#1335,.T.);
#1337=ORIENTED_EDGE('',*,*,#1336,.T.);
#1338=ORIENTED_EDGE('',*,*,#553,.T.);
#1339=EDGE_LOOP('',(#1329,#1330,#1331,#1337,#1338));
#1340=FACE_BOUND('',#1339,.T.);
#1341=ADVANCED_FACE('F778',(#1340),#1328,.F.);
#1342=CARTESIAN_POINT('',(-1.61121766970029E-10,0.,0.));
#1343=DIRECTION('',(1.,0.,0.));
#1344=DIRECTION('',(0.,0.,-1.));
#1345=AXIS2_PLACEMENT_3D('',#1342,#1343,#1344);
#1346=CYLINDRICAL_SURFACE('',#1345,5.413375);
#1347=ORIENTED_EDGE('',*,*,#562,.T.);
#1348=ORIENTED_EDGE('',*,*,#1336,.F.);
#1349=ORIENTED_EDGE('',*,*,#965,.F.);
#1350=DIRECTION('',(1.,0.,0.));
#1351=VECTOR('',#1350,1.);
#1352=CARTESIAN_POINT('',(-1.61121766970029E-10,-5.36186305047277,0.745019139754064));
#1353=LINE('',#1352,#1351);
#1354=EDGE_CURVE('E340',#955,#561,#1353,.T.);
#1355=ORIENTED_EDGE('',*,*,#1354,.T.);
#1356=EDGE_LOOP('',(#1347,#1348,#1349,#1355));
#1357=FACE_BOUND('',#1356,.T.);
#1358=ADVANCED_FACE('F781',(#1357),#1346,.T.);
#1359=CARTESIAN_POINT('',(-1.61121766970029E-10,-5.36186305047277,0.745019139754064));
#1360=DIRECTION('',(0.,0.,-1.));
#1361=DIRECTION('',(0.,1.,0.));
#1362=AXIS2_PLACEMENT_3D('',#1359,#1360,#1361);
#1363=PLANE('',#1362);
#1364=ORIENTED_EDGE('',*,*,#230,.T.);
#1365=ORIENTED_EDGE('',*,*,#568,.T.);
#1366=ORIENTED_EDGE('',*,*,#1354,.F.);
#1367=ORIENTED_EDGE('',*,*,#956,.F.);
#1368=ORIENTED_EDGE('',*,*,#383,.F.);
#1369=EDGE_LOOP('',(#1364,#1365,#1366,#1367,#1368));
#1370=FACE_BOUND('',#1369,.T.);
#1371=ADVANCED_FACE('F790',(#1370),#1363,.F.);
#1372=CARTESIAN_POINT('',(-1.61121766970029E-10,3.26460163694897,4.31821780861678));
#1373=DIRECTION('',(0.,0.707106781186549,-0.707106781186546));
#1374=DIRECTION('',(0.,0.707106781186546,0.707106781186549));
#1375=AXIS2_PLACEMENT_3D('',#1372,#1373,#1374);
#1376=PLANE('',#1375);
#1377=ORIENTED_EDGE('',*,*,#35,.T.);
#1378=ORIENTED_EDGE('',*,*,#276,.F.);
#1379=ORIENTED_EDGE('',*,*,#822,.F.);
#1380=DIRECTION('',(1.,0.,0.));
#1381=VECTOR('',#1380,1.);
#1382=CARTESIAN_POINT('',(-1.61121766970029E-10,3.26460163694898,4.31821780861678));
#1383=LINE('',#1382,#1381);
#1384=EDGE_CURVE('E317',#821,#504,#1383,.T.);
#1385=ORIENTED_EDGE('',*,*,#1384,.T.);
#1386=ORIENTED_EDGE('',*,*,#505,.T.);
#1387=EDGE_LOOP('',(#1377,#1378,#1379,#1385,#1386));
#1388=FACE_BOUND('',#1387,.T.);
#1389=ADVANCED_FACE('F795',(#1388),#1376,.F.);
#1390=CARTESIAN_POINT('',(-1.61121766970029E-10,0.,0.));
#1391=DIRECTION('',(1.,0.,0.));
#1392=DIRECTION('',(0.,0.,-1.));
#1393=AXIS2_PLACEMENT_3D('',#1390,#1391,#1392);
#1394=CYLINDRICAL_SURFACE('',#1393,5.413375);
#1395=ORIENTED_EDGE('',*,*,#514,.T.);
#1396=ORIENTED_EDGE('',*,*,#1384,.F.);
#1397=ORIENTED_EDGE('',*,*,#1011,.F.);
#1398=DIRECTION('',(1.,0.,0.));
#1399=VECTOR('',#1398,1.);
#1400=CARTESIAN_POINT('',(-1.61121766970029E-10,0.745019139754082,5.36186305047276));
#1401=LINE('',#1400,#1399);
#1402=EDGE_CURVE('E307',#1003,#513,#1401,.T.);
#1403=ORIENTED_EDGE('',*,*,#1402,.T.);
#1404=EDGE_LOOP('',(#1395,#1396,#1397,#1403));
#1405=FACE_BOUND('',#1404,.T.);
#1406=ADVANCED_FACE('F319',(#1405),#1394,.T.);
#1407=CARTESIAN_POINT('',(-1.61121766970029E-10,0.745019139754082,5.36186305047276));
#1408=DIRECTION('',(0.,-1.,0.));
#1409=DIRECTION('',(0.,0.,-1.));
#1410=AXIS2_PLACEMENT_3D('',#1407,#1408,#1409);
#1411=PLANE('',#1410);
#1412=ORIENTED_EDGE('',*,*,#115,.T.);
#1413=ORIENTED_EDGE('',*,*,#520,.T.);
#1414=ORIENTED_EDGE('',*,*,#1402,.F.);
#1415=ORIENTED_EDGE('',*,*,#1004,.F.);
#1416=ORIENTED_EDGE('',*,*,#317,.F.);
#1417=EDGE_LOOP('',(#1412,#1413,#1414,#1415,#1416));
#1418=FACE_BOUND('',#1417,.T.);
#1419=ADVANCED_FACE('F309',(#1418),#1411,.F.);
#1420=CLOSED_SHELL('',(#66,#99,#140,#181,#214,#255,#287,#309,#331,#353,#375,#397,#438,#460,#493,
#704,#724,#744,#753,#770,#790,#810,#1018,#1035,#1053,#1070,#1083,#1101,#1118,#1131,#1149,#1166,
#1179,#1197,#1214,#1227,#1245,#1262,#1275,#1293,#1310,#1323,#1341,#1358,#1371,#1389,#1406,#1419));
#1421=MANIFOLD_SOLID_BREP('B2',#1420);
#1422=ADVANCED_BREP_SHAPE_REPRESENTATION('',(#18,#1421),#14);
#1423=SHAPE_DEFINITION_REPRESENTATION(#9,#1422);
ENDSEC;
END-ISO-10303-21;
